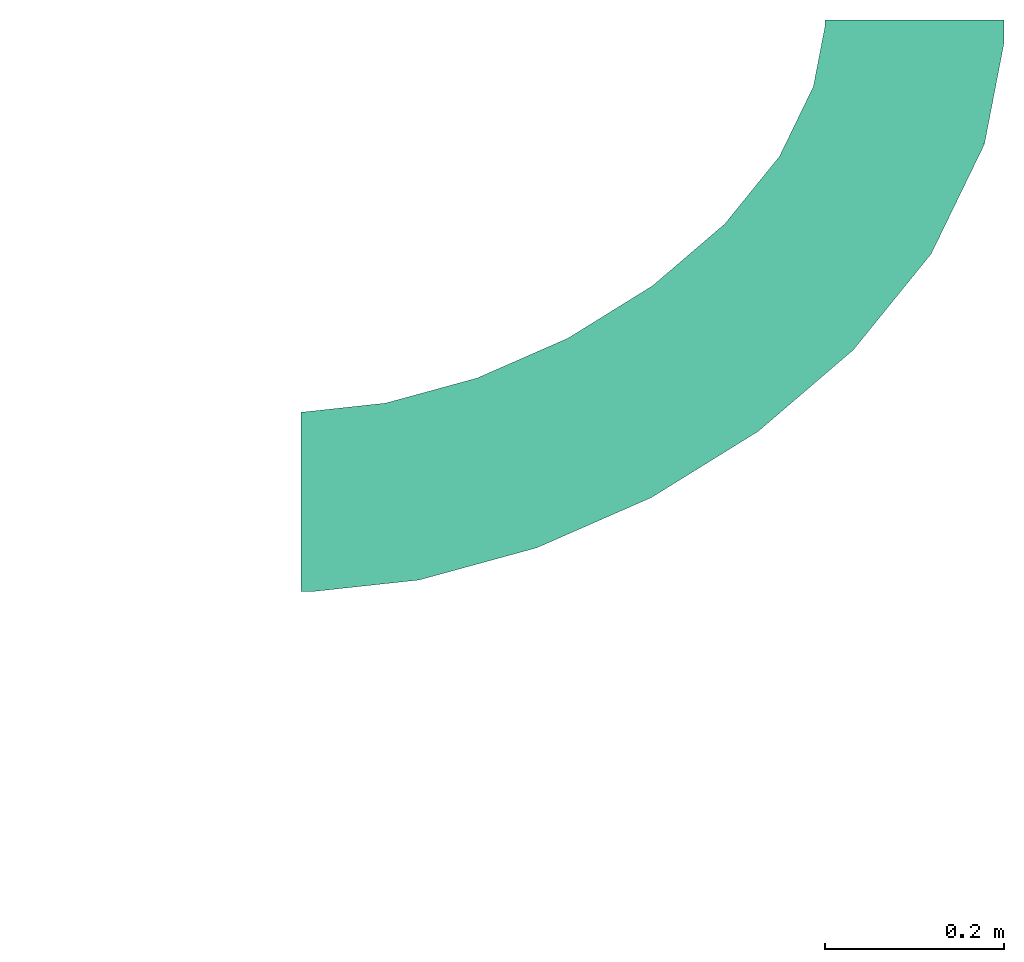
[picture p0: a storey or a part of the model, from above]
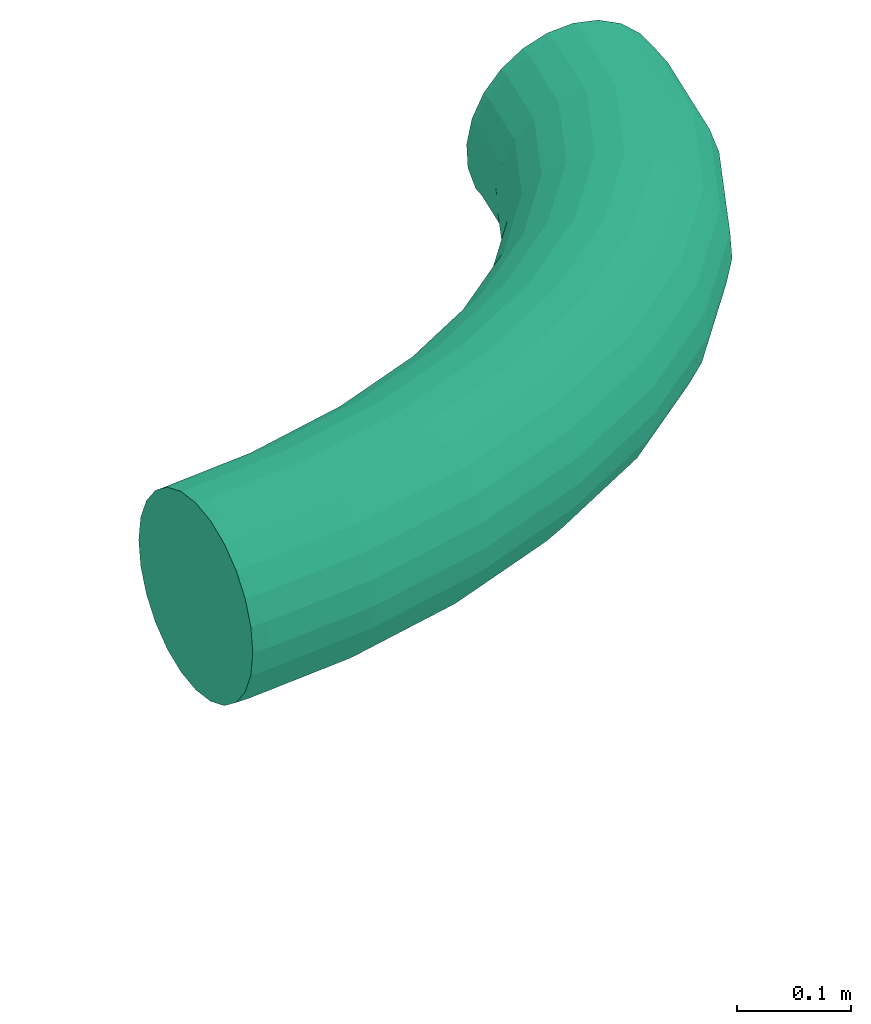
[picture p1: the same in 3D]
Properties of the parts of a building model (IFC2X3), part 1 of 2

# File
Description: ViewDefinition [CoordinationView_V2.0], RevitIdentifiers [ContentGUID: 55fdd698-1774-4c56-9708-9a2c424ac63d, VersionGUID: ae5423be-a13d-499d-9178-ae4d7e7fb8e4, NumberOfSaves: 309], CoordinateReference [CoordinateBase: Origem interna, ProjectSite: Terreno padrão]
File name: HVAC_ESCOLA DE CINEMA-CINE REX_01.ifc
Time: 2025-12-24T13:22:24-03:00
Written by: ODA SDAI 24.12
Made in: Autodesk Revit 25.3.0.46 (PTB) - IFC 25.3.0.46

# IfcProject, 0001
LongName: ESCOLA DE CINEMA E AUDIOVISUAL - CINE REX; Phase: AR CONDICIONADO

# IfcSite, Default
RefLatitude: -15, -52, 0, -120620; RefLongitude: -47, -55, 0, -114440; RefElevation: -6.76792e-14 mm

# IfcBuilding, Praça Pedro II, 1301 - Centro (Sul), Teresina - PI, 64001-100
LongName: Praça Pedro II, 1301 - Centro (Sul), Teresina - PI, 64001-100
Pset_BuildingCommon - NumberOfStoreys: 5

# IfcBuildingStorey: Nível:Cabeça de 8 mm (6)
In: Praça Pedro II, 1301 - Centro (Sul), Teresina - PI, 64001-100
Name | LongName | Elevation (mm)
TÉRREO -0.14m | TÉRREO -0.14m | -140
Nível 1 | Nível 1 | 0
TÉRREO +0.32m | TÉRREO +0.32m | 320
1PAV | 1PAV | 3020
2PAV | 2PAV | 6040
LAJE TÉCNICA | LAJE TÉCNICA | 9040

# IfcBuildingElementPart: QFACs:QFAC-1, QFACs:QFAC-1:884960
In: LAJE TÉCNICA
Type - Material: <Unnamed>
Pset_QuantityTakeOff - Reference: QFAC-1

# IfcBuildingElementProxy: Canvas Connection:Canvas Connection (8)
Type - Material: <Unnamed>
Pset_BuildingElementProxyCommon - Reference: Padrão; sets with these values: 2
Name (Canvas Connection:Padrão:...) | In
1067711 | 2PAV
1069002 | LAJE TÉCNICA
1069007 | LAJE TÉCNICA
1069011 | LAJE TÉCNICA
1069015 | LAJE TÉCNICA
1073034 | 1PAV
1084725 | 1PAV
1095775 | TÉRREO +0.32m

# IfcBuildingElementProxy: Família 40DV_Mod_Damper FanCoil:Tp05 40DV 670 (2)
In: LAJE TÉCNICA
Type - Material: <Unnamed>, Galvanizado
Type - Pset_ManufacturerTypeInformation - Manufacturer: Carrier do Brasil
Pset_BuildingElementProxyCommon - Reference: Tp05 40DV 670; sets with these values: 2
Name (Família 40DV_Mod_Damper FanCoil:Tp05 40DV 670:...)
872556
872802

# IfcBuildingElementProxy: Família 40DV_Mod_Troc_Vent FanCoil:Tp05 39DV 670 (2)
In: LAJE TÉCNICA
Type - Material: Galvanizado, Branco, Azul, <Unnamed>
Type - Pset_ManufacturerTypeInformation - Manufacturer: Carrier do Brasil
Pset_BuildingElementProxyCommon - Reference: Tp05 39DV 670; sets with these values: 2
Name (Família 40DV_Mod_Troc_Vent FanCoil:Tp05 39DV 670:...)
872605
872803

# IfcBuildingElementProxy: GLPF-200_1000-H-B-G4_M5:GLPF 280 (2)
In: LAJE TÉCNICA
Type - Material: Steel, Galvanized, Fabric
Type - Pset_ManufacturerTypeInformation - Manufacturer: Sicflux
Pset_BuildingElementProxyCommon - Reference: GLPF 280; sets with these values: 2
Name (GLPF-200_1000-H-B-G4_M5:GLPF 280:...) | Group
1087751 | AE 23
1088407 | AE 26

# IfcBuildingElementProxy: MIH100(140)DLHN18 (provisório):MIH160DLHN18, MIH100(140)DLHN18 (provisório):MIH160DLHN18:784083
In: 2PAV
Type - Material: Galvanized Steel, <Unnamed>
Pset_BuildingElementProxyCommon - Reference: MIH160DLHN18; sets with these values: 2

# IfcBuildingElementProxy: MULT VORTEX PAREDE:Tipo 1, MULT VORTEX PAREDE:Tipo 1:1112884
In: TÉRREO +0.32m
Type - Material: INOX ESCOVADO, INOX
Pset_BuildingElementProxyCommon - Reference: Tipo 1; sets with these values: 2
Group: EX 11

# IfcBuildingElementProxy: M_Control Damper - Opposed Blade (Type):100X105, M_Control Damper - Opposed Blade (Type):100X105:923647
In: TÉRREO +0.32m
Type - Material: <Unnamed>
Pset_BuildingElementProxyCommon - Reference: 100X105; sets with these values: 2
Group: AE 23

# IfcBuildingElementProxy: M_Control Damper - Opposed Blade (Type):100X155, M_Control Damper - Opposed Blade (Type):100X155:951628
In: 2PAV
Type - Material: <Unnamed>
Pset_BuildingElementProxyCommon - Reference: 100X155; sets with these values: 2
Group: AE 2

# IfcBuildingElementProxy: M_Control Damper - Opposed Blade (Type):200x155, M_Control Damper - Opposed Blade (Type):200x155:1071531
In: 1PAV
Type - Material: <Unnamed>
Pset_BuildingElementProxyCommon - Reference: 200x155; sets with these values: 2
Group: AE 13

# IfcBuildingElementProxy: Midea_VRF_Outdoor_MVCMax-M615(670,730,785,850)WV2GN1(50_60Hz):MVC-M670WV2GN1 (2)
In: LAJE TÉCNICA
Type - Material: Galvanized Steel
Type - Pset_ManufacturerTypeInformation - Manufacturer: Midea
Material: <Unnamed>, White, Dark Blue, Galvanized Steel
Pset_BuildingElementProxyCommon - Reference: MVC-M670WV2GN1; sets with these values: 2
Name (Midea_VRF_Outdoor_MVCMax-M615(670,730,785,850)WV2GN1(50_60Hz):MVC-M670WV2GN1:...)
792057
792070

# IfcBuildingElementProxy: Midea_VRF_Outdoor_MVCMax-M615(670,730,785,850)WV2GN1(50_60Hz):MVC-M785WV2GN1 (3)
In: LAJE TÉCNICA
Type - Material: Galvanized Steel
Type - Pset_ManufacturerTypeInformation - Manufacturer: Midea
Material: <Unnamed>, White, Dark Blue, Galvanized Steel
Pset_BuildingElementProxyCommon - Reference: MVC-M785WV2GN1; sets with these values: 2
Name (Midea_VRF_Outdoor_MVCMax-M615(670,730,785,850)WV2GN1(50_60Hz):MVC-M785WV2GN1:...)
792090
792099
883997

# IfcBuildingElementProxy: SGSD 277_457:SGSD 277, SGSD 277_457:SGSD 277:1084501
In: 1PAV
Type - Material: Steel, Galvanized
Type - Pset_ManufacturerTypeInformation - Manufacturer: Sicflux
Pset_BuildingElementProxyCommon - Reference: SGSD 277; sets with these values: 2
Group: AE 13; AE 24

# IfcBuildingElementProxy: SPLITVENT_BTS:SPLITVENT G4+M5, SPLITVENT_BTS:SPLITVENT G4+M5:1081998
In: 2PAV
Type - Material: Acetinado, Centra Fan - Body
Pset_BuildingElementProxyCommon - Reference: SPLITVENT G4+M5; sets with these values: 2

# IfcBuildingElementProxy: V8 Hi Wall 1.5-3.6kW Revit:2.2kW, V8 Hi Wall 1.5-3.6kW Revit:2.2kW:864359
In: TÉRREO +0.32m
Type - Material: Galvanized Steel, <Unnamed>
Pset_BuildingElementProxyCommon - Reference: 2.2kW; sets with these values: 2

# IfcBuildingElementProxy: V8 Hi Wall 1.5-3.6kW Revit:2.8kW (2)
Type - Material: Galvanized Steel, <Unnamed>
Pset_BuildingElementProxyCommon - Reference: 2.8kW; sets with these values: 2
Name (V8 Hi Wall 1.5-3.6kW Revit:2.8kW:...) | In
770520 | TÉRREO +0.32m
872139 | 2PAV

# IfcBuildingElementProxy: V8 Hi Wall 1.5-3.6kW Revit:3.6kW, V8 Hi Wall 1.5-3.6kW Revit:3.6kW:948295
In: 2PAV
Type - Material: Galvanized Steel, <Unnamed>
Pset_BuildingElementProxyCommon - Reference: 3.6kW; sets with these values: 2

# IfcBuildingElementProxy: V8 K7 4V 16.0-18.0kW:MIH160Q4HN18 (2)
Type - Material: Midea White, grilles：ABS/HIPS
Pset_BuildingElementProxyCommon - Reference: MIH160Q4HN18; sets with these values: 2
Name (V8 K7 4V 16.0-18.0kW:MIH160Q4HN18:...) | In
753553 | TÉRREO +0.32m
936077 | 2PAV

# IfcBuildingElementProxy: V8 K7 4V 2.8-8.0kW:MIH28Q4HN18, V8 K7 4V 2.8-8.0kW:MIH28Q4HN18:872213
In: 2PAV
Type - Material: Midea White, grilles：ABS/HIPS
Pset_BuildingElementProxyCommon - Reference: MIH28Q4HN18; sets with these values: 2

# IfcBuildingElementProxy: V8 K7 4V 2.8-8.0kW:MIH45Q4HN18, V8 K7 4V 2.8-8.0kW:MIH45Q4HN18:784014
In: 2PAV
Type - Material: Midea White, grilles：ABS/HIPS
Pset_BuildingElementProxyCommon - Reference: MIH45Q4HN18; sets with these values: 2

# IfcBuildingElementProxy: V8 K7 4V 2.8-8.0kW:MIH56Q4HN18, V8 K7 4V 2.8-8.0kW:MIH56Q4HN18:871980
In: 2PAV
Type - Material: Midea White, grilles：ABS/HIPS
Pset_BuildingElementProxyCommon - Reference: MIH56Q4HN18; sets with these values: 2

# IfcBuildingElementProxy: V8 K7 4V 9.0-14.0kW:MIH100Q4HN18 (5)
In: 1PAV
Type - Material: Midea White, grilles：ABS/HIPS
Type - Pset_ManufacturerTypeInformation - Manufacturer: Midea
Pset_BuildingElementProxyCommon - Reference: MIH100Q4HN18; sets with these values: 2
Name (V8 K7 4V 9.0-14.0kW:MIH100Q4HN18:...)
780288
780299
869001
869040
869052

# IfcBuildingElementProxy: V8 K7 4V 9.0-14.0kW:MIH112Q4HN18 (3)
Type - Material: Midea White, grilles：ABS/HIPS
Type - Pset_ManufacturerTypeInformation - Manufacturer: Midea
Pset_BuildingElementProxyCommon - Reference: MIH112Q4HN18; sets with these values: 2
Name (V8 K7 4V 9.0-14.0kW:MIH112Q4HN18:...) | In
784062 | 2PAV
841499 | 1PAV
841638 | 1PAV

# IfcBuildingElementProxy: V8 One-way cassette 1.8-3.6kW Revit:2.8kW, V8 One-way cassette 1.8-3.6kW Revit:2.8kW:842424
In: 2PAV
Type - Material: grilles：ABS/HIPS
Pset_BuildingElementProxyCommon - Reference: 2.8kW; sets with these values: 2

# IfcBuildingElementProxy: V8 One-way cassette 4.5-7.1kW Revit:4.5kW (2)
In: 2PAV
Type - Material: grilles：ABS/HIPS
Pset_BuildingElementProxyCommon - Reference: 4.5kW; sets with these values: 2
Name (V8 One-way cassette 4.5-7.1kW Revit:4.5kW:...)
842263
872043

# IfcBuildingElementProxy: V8 One-way cassette 4.5-7.1kW Revit:7.1kW (3)
Type - Material: grilles：ABS/HIPS
Pset_BuildingElementProxyCommon - Reference: 7.1kW; sets with these values: 2
Name (V8 One-way cassette 4.5-7.1kW Revit:7.1kW:...) | In
765319 | TÉRREO +0.32m
842596 | 2PAV
864236 | TÉRREO +0.32m

# IfcBuildingElementProxy: V8 duto alta 20-33.5kW:28kW (2)
Type - Material: Galvanized Steel, grilles：ABS/HIPS
Pset_BuildingElementProxyCommon - Reference: 28kW; sets with these values: 2
Name (V8 duto alta 20-33.5kW:28kW:...) | In | Group
869751 | 2PAV | R 5
882826 | 1PAV | I 5

# IfcBuildingElementProxy: V8 duto média 11.2-16.0kW:11.2kW, V8 duto média 11.2-16.0kW:11.2kW:868180
In: TÉRREO +0.32m
Type - Material: grilles：ABS/HIPS
Pset_BuildingElementProxyCommon - Reference: 11.2kW; sets with these values: 2
Group: R 3; I 8

# IfcBuildingElementProxy: VENTILADOR Titan LSC e LSF 200 a 1250:224 LSC (2)
In: LAJE TÉCNICA
Type - Material: VENTILADOS SIC, <Unnamed>, PRETO, cinza
Pset_BuildingElementProxyCommon - Reference: 224 LSC; sets with these values: 2
Name (VENTILADOR Titan LSC e LSF 200 a 1250:224 LSC:...) | Group
1063111 | EX 8; AE 20
1063151 | EX 3; AE 21

# IfcBuildingElementProxy: VENTILADOR Titan LSC e LSF 200 a 1250:250 LSC (2)
In: LAJE TÉCNICA
Type - Material: VENTILADOS SIC, <Unnamed>, PRETO, cinza
Pset_BuildingElementProxyCommon - Reference: 250 LSC; sets with these values: 2
Name (VENTILADOR Titan LSC e LSF 200 a 1250:250 LSC:...) | Group
1062948 | EX 1; AE 18
1063103 | EX 9; AE 19

# IfcBuildingElementProxy: VENTILADOR Titan LSC e LSF 200 a 1250:280 LSC, VENTILADOR Titan LSC e LSF 200 a 1250:280 LSC:1064072
In: LAJE TÉCNICA
Type - Material: VENTILADOS SIC, <Unnamed>, PRETO, cinza
Pset_BuildingElementProxyCommon - Reference: 280 LSC; sets with these values: 2
Group: EX 2; AE 22

# IfcBuildingElementProxy: VENTILADOR Titan LSC e LSF 200 a 1250:450 LSC, VENTILADOR Titan LSC e LSF 200 a 1250:450 LSC:1114082
In: LAJE TÉCNICA
Type - Material: VENTILADOS SIC, <Unnamed>, PRETO, cinza
Pset_BuildingElementProxyCommon - Reference: 450 LSC; sets with these values: 2
Group: EX 11; EX 10

# IfcDistributionPort (1531)
Description: Flow
Name | FlowDirection | Group
OutPort_753553_5 | SOURCE
Port_753553_6 | SOURCEANDSINK
Port_753553_7 | SOURCEANDSINK
Port_753553_8 | SOURCEANDSINK
Port_765319_4 | SOURCEANDSINK
Port_765319_5 | SOURCEANDSINK
OutPort_765319_6 | SOURCE
Port_765319_7 | SOURCEANDSINK
OutPort_770520_5 | SOURCE
Port_770520_6 | SOURCEANDSINK
Port_770520_7 | SOURCEANDSINK
Port_770520_8 | SOURCEANDSINK
OutPort_780288_5 | SOURCE
Port_780288_6 | SOURCEANDSINK
Port_780288_7 | SOURCEANDSINK
Port_780288_8 | SOURCEANDSINK
OutPort_780299_5 | SOURCE
Port_780299_6 | SOURCEANDSINK
Port_780299_7 | SOURCEANDSINK
Port_780299_8 | SOURCEANDSINK
OutPort_784014_5 | SOURCE
Port_784014_6 | SOURCEANDSINK
Port_784014_7 | SOURCEANDSINK
Port_784014_8 | SOURCEANDSINK
OutPort_784062_5 | SOURCE
Port_784062_6 | SOURCEANDSINK
Port_784062_7 | SOURCEANDSINK
Port_784062_8 | SOURCEANDSINK
OutPort_784083_5 | SOURCE
Port_784083_6 | SOURCEANDSINK
Port_784083_9 | SOURCEANDSINK
Port_792057_18 | SOURCEANDSINK
Port_792057_19 | SOURCEANDSINK
Port_792057_20 | SOURCEANDSINK
Port_792070_18 | SOURCEANDSINK
Port_792070_19 | SOURCEANDSINK
Port_792070_20 | SOURCEANDSINK
Port_792090_18 | SOURCEANDSINK
Port_792090_19 | SOURCEANDSINK
Port_792090_20 | SOURCEANDSINK
Port_792099_18 | SOURCEANDSINK
Port_792099_19 | SOURCEANDSINK
Port_792099_20 | SOURCEANDSINK
InPort_806109_2 | SINK | Mecânica Ar de fornecimento 1
OutPort_819979_0 | SOURCE | Mecânica Ar de fornecimento 1
InPort_806130_2 | SINK | Mecânica Ar de fornecimento 1
OutPort_819983_0 | SOURCE | Mecânica Ar de fornecimento 1
InPort_806138_2 | SINK | I 1
OutPort_820243_0 | SOURCE | I 1
InPort_806146_2 | SINK | I 1
OutPort_820247_1 | SOURCE | I 1
InPort_806156_2 | SINK | I 1
OutPort_820250_0 | SOURCE | I 1
InPort_806166_2 | SINK | I 1
OutPort_820259_0 | SOURCE | I 1
InPort_806176_2 | SINK | I 1
OutPort_820262_0 | SOURCE | I 1
InPort_806184_2 | SINK | I 1
OutPort_820271_0 | SOURCE | I 1
InPort_806205_2 | SINK | I 1
OutPort_820253_0 | SOURCE | I 1
InPort_806206_2 | SINK | I 1
OutPort_820256_0 | SOURCE | I 1
InPort_806207_2 | SINK | I 1
OutPort_820265_0 | SOURCE | I 1
InPort_806208_2 | SINK | I 1
OutPort_820268_0 | SOURCE | I 1
InPort_806216_2 | SINK | Mecânica Ar de fornecimento 1
OutPort_819986_0 | SOURCE | Mecânica Ar de fornecimento 1
InPort_806217_2 | SINK | Mecânica Ar de fornecimento 1
OutPort_819995_0 | SOURCE | Mecânica Ar de fornecimento 1
InPort_806218_2 | SINK | Mecânica Ar de fornecimento 1
OutPort_819998_0 | SOURCE | Mecânica Ar de fornecimento 1
InPort_806219_2 | SINK | Mecânica Ar de fornecimento 1
OutPort_820007_0 | SOURCE | Mecânica Ar de fornecimento 1
InPort_806227_2 | SINK | Mecânica Ar de fornecimento 1
OutPort_819989_0 | SOURCE | Mecânica Ar de fornecimento 1
InPort_806228_2 | SINK | Mecânica Ar de fornecimento 1
OutPort_819992_0 | SOURCE | Mecânica Ar de fornecimento 1
InPort_806229_2 | SINK | Mecânica Ar de fornecimento 1
OutPort_820001_0 | SOURCE | Mecânica Ar de fornecimento 1
InPort_806230_2 | SINK | Mecânica Ar de fornecimento 1
OutPort_820004_0 | SOURCE | Mecânica Ar de fornecimento 1
InPort_874549_1 | SINK | Mecânica Ar de fornecimento 1
OutPort_818453_0 | SOURCE | Mecânica Ar de fornecimento 1
InPort_818453_1 | SINK | Mecânica Ar de fornecimento 1
OutPort_873457_1 | SOURCE | Mecânica Ar de fornecimento 1
InPort_818453_4 | SINK | Mecânica Ar de fornecimento 1
OutPort_873459_1 | SOURCE | Mecânica Ar de fornecimento 1
InPort_818453_5 | SINK | Mecânica Ar de fornecimento 1
OutPort_873462_1 | SOURCE | Mecânica Ar de fornecimento 1
InPort_873556_1 | SINK | I 1
OutPort_818485_0 | SOURCE | I 1
InPort_818485_1 | SINK | I 1
OutPort_873502_1 | SOURCE | I 1
InPort_818485_4 | SINK | I 1
OutPort_873503_1 | SOURCE | I 1
InPort_818485_5 | SINK | I 1
OutPort_873505_1 | SOURCE | I 1
InPort_873457_2 | SINK | Mecânica Ar de fornecimento 1
OutPort_818510_0 | SOURCE | Mecânica Ar de fornecimento 1
InPort_818510_1 | SINK | Mecânica Ar de fornecimento 1
OutPort_873441_2 | SOURCE | Mecânica Ar de fornecimento 1
InPort_818510_2 | SINK | I 2
OutPort_819832_1 | SOURCE | I 2
InPort_818510_3 | SINK | I 2
OutPort_819874_1 | SOURCE | I 2
InPort_873502_2 | SINK | I 1
OutPort_818544_0 | SOURCE | I 1
InPort_818544_1 | SINK | I 1
OutPort_873513_2 | SOURCE | I 1
InPort_818544_2 | SINK | I 3
OutPort_820118_1 | SOURCE | I 3
InPort_818544_3 | SINK | I 3
OutPort_820128_1 | SOURCE | I 3
InPort_873441_1 | SINK | Mecânica Ar de fornecimento 1
OutPort_818567_0 | SOURCE | Mecânica Ar de fornecimento 1
InPort_818567_1 | SINK | Mecânica Ar de fornecimento 1
OutPort_873442_1 | SOURCE | Mecânica Ar de fornecimento 1
InPort_818567_4 | SINK | Mecânica Ar de fornecimento 1
OutPort_873444_1 | SOURCE | Mecânica Ar de fornecimento 1
InPort_818567_5 | SINK | Mecânica Ar de fornecimento 1
OutPort_873447_1 | SOURCE | Mecânica Ar de fornecimento 1
InPort_873513_1 | SINK | I 1
OutPort_818605_0 | SOURCE | I 1
InPort_818605_1 | SINK | I 1
OutPort_873514_1 | SOURCE | I 1
InPort_818605_2 | SINK | I 1
OutPort_876320_1 | SOURCE | I 1
InPort_818605_3 | SINK | I 1
OutPort_876328_1 | SOURCE | I 1
InPort_819832_1 | SINK | Mecânica Ar de fornecimento 1
OutPort_818510_2 | SOURCE | Mecânica Ar de fornecimento 1
InPort_819992_1 | SINK | Mecânica Ar de fornecimento 1
OutPort_819832_2 | SOURCE | Mecânica Ar de fornecimento 1
InPort_819874_1 | SINK | Mecânica Ar de fornecimento 1
OutPort_818510_3 | SOURCE | Mecânica Ar de fornecimento 1
InPort_819995_1 | SINK | Mecânica Ar de fornecimento 1
OutPort_819874_2 | SOURCE | Mecânica Ar de fornecimento 1
InPort_819979_1 | SINK | Mecânica Ar de fornecimento 1
OutPort_876085_2 | SOURCE | Mecânica Ar de fornecimento 1
InPort_819983_1 | SINK | Mecânica Ar de fornecimento 1
OutPort_876095_2 | SOURCE | Mecânica Ar de fornecimento 1
InPort_819986_1 | SINK | Mecânica Ar de fornecimento 1
OutPort_873459_2 | SOURCE | Mecânica Ar de fornecimento 1
InPort_819989_1 | SINK | Mecânica Ar de fornecimento 1
OutPort_873462_2 | SOURCE | Mecânica Ar de fornecimento 1
InPort_819998_1 | SINK | Mecânica Ar de fornecimento 1
OutPort_873444_2 | SOURCE | Mecânica Ar de fornecimento 1
InPort_820001_1 | SINK | Mecânica Ar de fornecimento 1
OutPort_873447_2 | SOURCE | Mecânica Ar de fornecimento 1
InPort_820004_1 | SINK | Mecânica Ar de fornecimento 1
OutPort_873420_2 | SOURCE | Mecânica Ar de fornecimento 1
InPort_820007_1 | SINK | Mecânica Ar de fornecimento 1
OutPort_873423_2 | SOURCE | Mecânica Ar de fornecimento 1
InPort_820118_1 | SINK | I 1
OutPort_818544_2 | SOURCE | I 1
InPort_820259_1 | SINK | I 1
OutPort_820118_2 | SOURCE | I 1
InPort_820128_1 | SINK | I 1
OutPort_818544_3 | SOURCE | I 1
InPort_820256_1 | SINK | I 1
OutPort_820128_2 | SOURCE | I 1
InPort_820243_1 | SINK | I 1
OutPort_876275_2 | SOURCE | I 1
InPort_820247_0 | SINK | I 1
OutPort_876241_2 | SOURCE | I 1
InPort_820250_1 | SINK | I 1
OutPort_873503_2 | SOURCE | I 1
InPort_820253_1 | SINK | I 1
OutPort_873505_2 | SOURCE | I 1
InPort_820262_1 | SINK | I 1
OutPort_876320_2 | SOURCE | I 1
InPort_820265_1 | SINK | I 1
OutPort_876328_2 | SOURCE | I 1
InPort_820268_1 | SINK | I 1
OutPort_874404_2 | SOURCE | I 1
InPort_820271_1 | SINK | I 1
OutPort_874430_2 | SOURCE | I 1
InPort_831728_1 | SINK | R 1
OutPort_829018_0 | SOURCE | R 1
Port_829018_1 | SOURCEANDSINK | R 1
Port_833313_1 | SOURCEANDSINK | R 1
InPort_829018_2 | SINK | R 1
OutPort_833305_1 | SOURCE | R 1
InPort_831641_1 | SINK | R 2
OutPort_829064_0 | SOURCE | R 2
Port_829064_1 | SOURCEANDSINK | R 2
Port_833358_1 | SOURCEANDSINK | R 2
InPort_829064_2 | SINK | R 2
OutPort_833351_1 | SOURCE | R 2
InPort_833251_0 | SINK | R 1
OutPort_830645_1 | SOURCE | R 1
InPort_833273_0 | SINK | R 1
OutPort_830682_1 | SOURCE | R 1
InPort_833288_0 | SINK | R 1
OutPort_830692_1 | SOURCE | R 1
InPort_833299_0 | SINK | R 1
OutPort_830700_1 | SOURCE | R 1
InPort_833347_0 | SINK | R 2
OutPort_830708_1 | SOURCE | R 2
InPort_833338_0 | SINK | R 2
OutPort_830732_1 | SOURCE | R 2
InPort_833329_0 | SINK | R 2
OutPort_830742_1 | SOURCE | R 2
InPort_833319_0 | SINK | R 2
OutPort_830750_1 | SOURCE | R 2
InPort_831099_0 | SINK | R 1
OutPort_831749_2 | SOURCE | R 1
InPort_878438_1 | SINK | R 1
OutPort_831099_1 | SOURCE | R 1
InPort_833259_1 | SINK | R 1
OutPort_831099_2 | SOURCE | R 1
InPort_831170_0 | SINK | R 1
OutPort_831748_2 | SOURCE | R 1
InPort_831749_1 | SINK | R 1
OutPort_831170_1 | SOURCE | R 1
InPort_833279_1 | SINK | R 1
OutPort_831170_2 | SOURCE | R 1
InPort_831225_0 | SINK | R 1
OutPort_831728_2 | SOURCE | R 1
InPort_831748_1 | SINK | R 1
OutPort_831225_1 | SOURCE | R 1
InPort_833294_1 | SINK | R 1
OutPort_831225_2 | SOURCE | R 1
InPort_831469_0 | SINK | R 2
OutPort_831686_2 | SOURCE | R 2
InPort_831687_1 | SINK | R 2
OutPort_831469_1 | SOURCE | R 2
InPort_833333_1 | SINK | R 2
OutPort_831469_2 | SOURCE | R 2
InPort_831545_0 | SINK | R 2
OutPort_831641_2 | SOURCE | R 2
InPort_831686_1 | SINK | R 2
OutPort_831545_1 | SOURCE | R 2
InPort_833342_1 | SINK | R 2
OutPort_831545_2 | SOURCE | R 2
InPort_875422_0 | SINK | R 2
OutPort_831687_2 | SOURCE | R 2
InPort_832806_0 | SINK | Mecânica Ar de fornecimento 1
OutPort_874549_2 | SOURCE | Mecânica Ar de fornecimento 1
Port_832806_1 | SOURCEANDSINK | Mecânica Ar de fornecimento 1
Port_874556_1 | SOURCEANDSINK | Mecânica Ar de fornecimento 1
InPort_876085_1 | SINK | Mecânica Ar de fornecimento 1
OutPort_832806_2 | SOURCE | Mecânica Ar de fornecimento 1
InPort_876095_1 | SINK | Mecânica Ar de fornecimento 1
OutPort_832806_3 | SOURCE | Mecânica Ar de fornecimento 1
InPort_832829_0 | SINK | I 1
OutPort_873556_2 | SOURCE | I 1
Port_832829_1 | SOURCEANDSINK | I 1
Port_875441_1 | SOURCEANDSINK | I 1
InPort_876241_1 | SINK | I 1
OutPort_832829_2 | SOURCE | I 1
InPort_876275_1 | SINK | I 1
OutPort_832829_3 | SOURCE | I 1
InPort_833259_2 | SINK | R 1
OutPort_833251_1 | SOURCE | R 1
InPort_831099_2 | SINK | R 1
OutPort_833259_1 | SOURCE | R 1
InPort_833279_2 | SINK | R 1
OutPort_833273_1 | SOURCE | R 1
InPort_831170_2 | SINK | R 1
OutPort_833279_1 | SOURCE | R 1
InPort_833294_2 | SINK | R 1
OutPort_833288_1 | SOURCE | R 1
InPort_831225_2 | SINK | R 1
OutPort_833294_1 | SOURCE | R 1
InPort_833305_2 | SINK | R 1
OutPort_833299_1 | SOURCE | R 1
InPort_833323_2 | SINK | R 2
OutPort_833319_1 | SOURCE | R 2
InPort_875422_2 | SINK | R 2
OutPort_833323_1 | SOURCE | R 2
InPort_833333_2 | SINK | R 2
OutPort_833329_1 | SOURCE | R 2
InPort_831469_2 | SINK | R 2
OutPort_833333_1 | SOURCE | R 2
InPort_833342_2 | SINK | R 2
OutPort_833338_1 | SOURCE | R 2
InPort_831545_2 | SINK | R 2
OutPort_833342_1 | SOURCE | R 2
InPort_833351_2 | SINK | R 2
OutPort_833347_1 | SOURCE | R 2
InPort_837886_1 | SINK | I 1
OutPort_837432_1 | SOURCE | I 1
InPort_837863_2 | SINK | I 1
OutPort_837524_1 | SOURCE | I 1
InPort_837854_0 | SINK | I 1
OutPort_837863_1 | SOURCE | I 1
InPort_838440_1 | SINK | I 1
OutPort_837854_1 | SOURCE | I 1
InPort_837879_0 | SINK | I 1
OutPort_837886_2 | SOURCE | I 1
InPort_838456_2 | SINK | I 1
OutPort_837879_1 | SOURCE | I 1
InPort_837887_0 | SINK | I 1
OutPort_838456_1 | SOURCE | I 1
InPort_838350_4 | SINK | I 1
OutPort_837887_1 | SOURCE | I 1
InPort_837912_0 | SINK | I 1
OutPort_838440_2 | SOURCE | I 1
InPort_838350_3 | SINK | I 1
OutPort_837912_1 | SOURCE | I 1
InPort_875039_1 | SINK | I 1
OutPort_838350_2 | SOURCE | I 1
InPort_838585_1 | SINK | Mecânica Ar de fornecimento 1
OutPort_838578_0 | SOURCE | Mecânica Ar de fornecimento 1
InPort_873376_2 | SINK | Mecânica Ar de fornecimento 1
OutPort_838579_0 | SOURCE | Mecânica Ar de fornecimento 1
InPort_838582_0 | SINK | Mecânica Ar de fornecimento 1
OutPort_873376_1 | SOURCE | Mecânica Ar de fornecimento 1
InPort_838589_1 | SINK | Mecânica Ar de fornecimento 1
OutPort_838582_1 | SOURCE | Mecânica Ar de fornecimento 1
InPort_838584_0 | SINK | Mecânica Ar de fornecimento 1
OutPort_838585_2 | SOURCE | Mecânica Ar de fornecimento 1
InPort_838590_2 | SINK | Mecânica Ar de fornecimento 1
OutPort_838584_1 | SOURCE | Mecânica Ar de fornecimento 1
InPort_838586_0 | SINK | Mecânica Ar de fornecimento 1
OutPort_838590_1 | SOURCE | Mecânica Ar de fornecimento 1
InPort_838588_4 | SINK | Mecânica Ar de fornecimento 1
OutPort_838586_1 | SOURCE | Mecânica Ar de fornecimento 1
InPort_838587_0 | SINK | Mecânica Ar de fornecimento 1
OutPort_838589_2 | SOURCE | Mecânica Ar de fornecimento 1
InPort_838588_3 | SINK | Mecânica Ar de fornecimento 1
OutPort_838587_1 | SOURCE | Mecânica Ar de fornecimento 1
InPort_838995_0 | SINK | Mecânica Ar de fornecimento 1
OutPort_838588_2 | SOURCE | Mecânica Ar de fornecimento 1
InPort_875176_1 | SINK | Mecânica Ar de fornecimento 1
OutPort_838995_1 | SOURCE | Mecânica Ar de fornecimento 1
OutPort_841499_5 | SOURCE
Port_841499_6 | SOURCEANDSINK
Port_841499_7 | SOURCEANDSINK
Port_841499_8 | SOURCEANDSINK
OutPort_841638_5 | SOURCE
Port_841638_6 | SOURCEANDSINK
Port_841638_7 | SOURCEANDSINK
Port_841638_8 | SOURCEANDSINK
Port_842263_4 | SOURCEANDSINK
Port_842263_5 | SOURCEANDSINK
OutPort_842263_6 | SOURCE
Port_842263_7 | SOURCEANDSINK
Port_842424_4 | SOURCEANDSINK
Port_842424_5 | SOURCEANDSINK
OutPort_842424_6 | SOURCE
Port_842424_7 | SOURCEANDSINK
Port_842596_4 | SOURCEANDSINK
Port_842596_5 | SOURCEANDSINK
OutPort_842596_6 | SOURCE
Port_842596_7 | SOURCEANDSINK
Port_864236_4 | SOURCEANDSINK
Port_864236_5 | SOURCEANDSINK
OutPort_864236_6 | SOURCE
Port_864236_7 | SOURCEANDSINK
OutPort_864359_5 | SOURCE
Port_864359_6 | SOURCEANDSINK
Port_864359_7 | SOURCEANDSINK
Port_864359_8 | SOURCEANDSINK
OutPort_868180_11 | SOURCE
Port_868180_16 | SOURCEANDSINK
Port_868180_17 | SOURCEANDSINK
Port_868180_18 | SOURCEANDSINK
Port_868180_21 | SOURCEANDSINK
Port_868180_22 | SOURCEANDSINK | R 3
Port_916132_0 | SOURCEANDSINK | R 3
Port_868180_23 | SOURCEANDSINK | I 8
OutPort_869001_5 | SOURCE
Port_869001_6 | SOURCEANDSINK
Port_869001_7 | SOURCEANDSINK
Port_869001_8 | SOURCEANDSINK
OutPort_869040_5 | SOURCE
Port_869040_6 | SOURCEANDSINK
Port_869040_7 | SOURCEANDSINK
Port_869040_8 | SOURCEANDSINK
OutPort_869052_5 | SOURCE
Port_869052_6 | SOURCEANDSINK
Port_869052_7 | SOURCEANDSINK
Port_869052_8 | SOURCEANDSINK
OutPort_869751_5 | SOURCE
InPort_869751_10 | SINK | R 5
OutPort_925507_0 | SOURCE | R 5
Port_869751_12 | SOURCEANDSINK
Port_869751_13 | SOURCEANDSINK
Port_869751_14 | SOURCEANDSINK
Port_869751_15 | SOURCEANDSINK
Port_869751_16 | SOURCEANDSINK
OutPort_871980_5 | SOURCE
Port_871980_6 | SOURCEANDSINK
Port_871980_7 | SOURCEANDSINK
Port_871980_8 | SOURCEANDSINK
Port_872043_4 | SOURCEANDSINK
Port_872043_5 | SOURCEANDSINK
OutPort_872043_6 | SOURCE
Port_872043_7 | SOURCEANDSINK
OutPort_872139_5 | SOURCE
Port_872139_6 | SOURCEANDSINK
Port_872139_7 | SOURCEANDSINK
Port_872139_8 | SOURCEANDSINK
OutPort_872213_5 | SOURCE
Port_872213_6 | SOURCEANDSINK
Port_872213_7 | SOURCEANDSINK
Port_872213_8 | SOURCEANDSINK
Port_872556_1 | SOURCEANDSINK
Port_872556_2 | SOURCEANDSINK
OutPort_872605_1 | SOURCE
InPort_872605_2 | SINK
OutPort_872605_4 | SOURCE
Port_872605_5 | SOURCEANDSINK
OutPort_872605_6 | SOURCE
Port_872605_11 | SOURCEANDSINK
OutPort_872605_12 | SOURCE
Port_872802_1 | SOURCEANDSINK
Port_872802_2 | SOURCEANDSINK
OutPort_872803_1 | SOURCE
InPort_872803_2 | SINK
OutPort_872803_4 | SOURCE
Port_872803_5 | SOURCEANDSINK
OutPort_872803_6 | SOURCE
Port_872803_11 | SOURCEANDSINK
OutPort_872803_12 | SOURCE
InPort_873420_1 | SINK | Mecânica Ar de fornecimento 1
OutPort_874741_3 | SOURCE | Mecânica Ar de fornecimento 1
InPort_873423_1 | SINK | Mecânica Ar de fornecimento 1
OutPort_874741_2 | SOURCE | Mecânica Ar de fornecimento 1
InPort_873442_2 | SINK | Mecânica Ar de fornecimento 1
OutPort_874741_0 | SOURCE | Mecânica Ar de fornecimento 1
InPort_873444_1 | SINK | Mecânica Ar de fornecimento 1
OutPort_818567_4 | SOURCE | Mecânica Ar de fornecimento 1
InPort_873447_1 | SINK | Mecânica Ar de fornecimento 1
OutPort_818567_5 | SOURCE | Mecânica Ar de fornecimento 1
InPort_873459_1 | SINK | Mecânica Ar de fornecimento 1
OutPort_818453_4 | SOURCE | Mecânica Ar de fornecimento 1
InPort_873462_1 | SINK | Mecânica Ar de fornecimento 1
OutPort_818453_5 | SOURCE | Mecânica Ar de fornecimento 1
InPort_873503_1 | SINK | I 1
OutPort_818485_4 | SOURCE | I 1
InPort_873505_1 | SINK | I 1
OutPort_818485_5 | SOURCE | I 1
InPort_873514_2 | SINK | I 1
OutPort_873656_0 | SOURCE | I 1
InPort_873656_1 | SINK | I 1
OutPort_874873_1 | SOURCE | I 1
InPort_873656_2 | SINK | I 1
OutPort_874404_1 | SOURCE | I 1
InPort_873656_3 | SINK | I 1
OutPort_874430_1 | SOURCE | I 1
InPort_874404_1 | SINK | I 1
OutPort_873656_2 | SOURCE | I 1
InPort_874430_1 | SINK | I 1
OutPort_873656_3 | SOURCE | I 1
InPort_874741_1 | SINK | Mecânica Ar de fornecimento 1
OutPort_874760_2 | SOURCE | Mecânica Ar de fornecimento 1
InPort_874741_2 | SINK | Mecânica Ar de fornecimento 1
OutPort_873423_1 | SOURCE | Mecânica Ar de fornecimento 1
InPort_874741_3 | SINK | Mecânica Ar de fornecimento 1
OutPort_873420_1 | SOURCE | Mecânica Ar de fornecimento 1
InPort_874760_1 | SINK | Mecânica Ar de fornecimento 1
OutPort_874750_0 | SOURCE | Mecânica Ar de fornecimento 1
InPort_874750_1 | SINK | Mecânica Ar de fornecimento 1
OutPort_874805_1 | SOURCE | Mecânica Ar de fornecimento 1
InPort_874805_2 | SINK | Mecânica Ar de fornecimento 1
OutPort_874806_0 | SOURCE | Mecânica Ar de fornecimento 1
InPort_874806_1 | SINK | Mecânica Ar de fornecimento 1
OutPort_875174_1 | SOURCE | Mecânica Ar de fornecimento 1
InPort_874873_2 | SINK | I 1
OutPort_874866_0 | SOURCE | I 1
InPort_874866_1 | SINK | I 1
OutPort_874880_2 | SOURCE | I 1
InPort_874880_1 | SINK | I 1
OutPort_874875_0 | SOURCE | I 1
InPort_874875_1 | SINK | I 1
OutPort_875036_1 | SOURCE | I 1
InPort_875036_2 | SINK | I 1
OutPort_875021_0 | SOURCE | I 1
InPort_875021_1 | SINK | I 1
OutPort_875070_1 | SOURCE | I 1
InPort_875070_2 | SINK | I 1
OutPort_875039_0 | SOURCE | I 1
InPort_875174_2 | SINK | Mecânica Ar de fornecimento 1
OutPort_875102_0 | SOURCE | Mecânica Ar de fornecimento 1
InPort_875102_1 | SINK | Mecânica Ar de fornecimento 1
OutPort_875176_2 | SOURCE | Mecânica Ar de fornecimento 1
InPort_878363_2 | SINK | R 2
OutPort_875422_1 | SOURCE | R 2
InPort_833323_1 | SINK | R 2
OutPort_875422_2 | SOURCE | R 2
InPort_876320_1 | SINK | I 1
OutPort_818605_2 | SOURCE | I 1
InPort_876328_1 | SINK | I 1
OutPort_818605_3 | SOURCE | I 1
InPort_878356_0 | SINK | R 2
OutPort_878363_1 | SOURCE | R 2
InPort_878412_1 | SINK | R 2
OutPort_878356_1 | SOURCE | R 2
InPort_878405_0 | SINK | R 2
OutPort_878412_2 | SOURCE | R 2
InPort_878595_1 | SINK | R 2
OutPort_878405_1 | SOURCE | R 2
InPort_878431_0 | SINK | R 1
OutPort_878438_2 | SOURCE | R 1
InPort_878444_2 | SINK | R 1
OutPort_878431_1 | SOURCE | R 1
InPort_878439_0 | SINK | R 1
OutPort_878444_1 | SOURCE | R 1
InPort_878476_1 | SINK | R 1
OutPort_878439_1 | SOURCE | R 1
InPort_878469_0 | SINK | R 1
OutPort_878476_2 | SOURCE | R 1
InPort_878857_1 | SINK | R 1
OutPort_878469_1 | SOURCE | R 1
InPort_1068476_1 | SINK | R 1
OutPort_878479_0 | SOURCE | R 1
InPort_878479_1 | SINK | R 1
OutPort_1068477_2 | SOURCE | R 1
InPort_878614_0 | SINK | R 2
OutPort_878595_2 | SOURCE | R 2
InPort_1068906_1 | SINK | R 2
OutPort_878614_1 | SOURCE | R 2
InPort_878816_0 | SINK | R 2
OutPort_878823_1 | SOURCE | R 2
OutPort_878816_1 | SOURCE | R 2
InPort_1068955_1 | SINK | R 2
OutPort_878816_2 | SOURCE | R 2
InPort_878823_2 | SINK | R 2
OutPort_1068919_0 | SOURCE | R 2
InPort_1068402_0 | SINK | R 1
OutPort_878857_2 | SOURCE | R 1
InPort_878860_0 | SINK | R 1
OutPort_1068476_2 | SOURCE | R 1
OutPort_878860_1 | SOURCE | R 1
InPort_1068689_1 | SINK | R 1
OutPort_878860_2 | SOURCE | R 1
OutPort_882826_5 | SOURCE
Port_882826_10 | SOURCEANDSINK
Port_882826_12 | SOURCEANDSINK
Port_882826_13 | SOURCEANDSINK
Port_882826_14 | SOURCEANDSINK | I 5
Port_882826_15 | SOURCEANDSINK
Port_882826_16 | SOURCEANDSINK | I 5
Port_883997_18 | SOURCEANDSINK
Port_883997_19 | SOURCEANDSINK
Port_883997_20 | SOURCEANDSINK
OutPort_888307_1 | SOURCE
OutPort_888325_1 | SOURCE
Port_894178_1 | SOURCEANDSINK | I 5
Port_895242_0 | SOURCEANDSINK | I 5
Port_894400_1 | SOURCEANDSINK | I 5
Port_895264_0 | SOURCEANDSINK | I 5
Port_894408_1 | SOURCEANDSINK | I 5
Port_895284_0 | SOURCEANDSINK | I 5
Port_894418_1 | SOURCEANDSINK | I 5
Port_895308_0 | SOURCEANDSINK | I 5
Port_894426_1 | SOURCEANDSINK | I 5
Port_895330_0 | SOURCEANDSINK | I 5
Port_894785_0 | SOURCEANDSINK | I 5
Port_895529_1 | SOURCEANDSINK | I 5
Port_894785_1 | SOURCEANDSINK | I 5
Port_895570_1 | SOURCEANDSINK | I 5
Port_894785_4 | SOURCEANDSINK | I 5
Port_895366_1 | SOURCEANDSINK | I 5
Port_894785_5 | SOURCEANDSINK | I 5
Port_895404_1 | SOURCEANDSINK | I 5
Port_894785_6 | SOURCEANDSINK | I 5
Port_895437_1 | SOURCEANDSINK | I 5
Port_894785_7 | SOURCEANDSINK | I 5
Port_895468_1 | SOURCEANDSINK | I 5
Port_894785_8 | SOURCEANDSINK | I 5
Port_895501_1 | SOURCEANDSINK | I 5
Port_894785_9 | SOURCEANDSINK | I 5
Port_1072892_1 | SOURCEANDSINK | I 5
Port_895242_1 | SOURCEANDSINK | I 5
Port_895501_2 | SOURCEANDSINK | I 5
Port_895264_1 | SOURCEANDSINK | I 5
Port_895468_2 | SOURCEANDSINK | I 5
Port_895284_1 | SOURCEANDSINK | I 5
Port_895437_2 | SOURCEANDSINK | I 5
Port_895308_1 | SOURCEANDSINK | I 5
Port_895404_2 | SOURCEANDSINK | I 5
Port_895330_1 | SOURCEANDSINK | I 5
Port_895366_2 | SOURCEANDSINK | I 5
InPort_896588_1 | SINK
InPort_898182_1 | SINK | AE 3
OutPort_923890_1 | SOURCE | AE 3
InPort_899065_1 | SINK | AE 3
OutPort_1124093_0 | SOURCE | AE 3
InPort_899070_1 | SINK | AE 3
OutPort_923757_0 | SOURCE | AE 3
InPort_899104_1 | SINK | AE 3
OutPort_1124044_0 | SOURCE | AE 3
InPort_899176_1 | SINK | AE 23
OutPort_924303_0 | SOURCE | AE 23
InPort_902440_1 | SINK | I 6
OutPort_910736_0 | SOURCE | I 6
InPort_902462_1 | SINK | I 6
OutPort_910820_0 | SOURCE | I 6
InPort_902470_1 | SINK | I 6
OutPort_910905_0 | SOURCE | I 6
InPort_902480_1 | SINK | I 6
OutPort_910989_0 | SOURCE | I 6
InPort_902786_0 | SINK | I 6
OutPort_902816_1 | SOURCE | I 6
Port_902786_1 | SOURCEANDSINK | I 6
Port_911081_1 | SOURCEANDSINK | I 6
InPort_911044_1 | SINK | I 6
OutPort_902786_2 | SOURCE | I 6
InPort_902816_2 | SINK | I 6
OutPort_902793_0 | SOURCE | I 6
InPort_902793_1 | SINK | I 6
OutPort_902839_1 | SOURCE | I 6
InPort_902793_2 | SINK | I 7
OutPort_910975_1 | SOURCE | I 7
InPort_902839_2 | SINK | I 6
OutPort_902818_0 | SOURCE | I 6
InPort_902818_1 | SINK | I 6
OutPort_902858_1 | SOURCE | I 6
InPort_902818_2 | SINK | I 4
OutPort_910890_1 | SOURCE | I 4
InPort_902858_2 | SINK | I 6
OutPort_903864_0 | SOURCE | I 6
InPort_903864_1 | SINK | I 6
OutPort_903880_2 | SOURCE | I 6
InPort_903864_2 | SINK | I 6
OutPort_910805_1 | SOURCE | I 6
InPort_903880_1 | SINK | I 6
OutPort_903871_0 | SOURCE | I 6
InPort_903871_1 | SINK | I 6
OutPort_903886_1 | SOURCE | I 6
InPort_903886_2 | SINK | I 6
OutPort_903881_0 | SOURCE | I 6
InPort_903881_1 | SINK | I 6
OutPort_925227_1 | SOURCE | I 6
InPort_904946_1 | SINK | EX 2
OutPort_912508_2 | SOURCE | EX 2
InPort_905042_1 | SINK | EX 2
OutPort_906717_0 | SOURCE | EX 2
InPort_905049_1 | SINK | EX 3
OutPort_906687_0 | SOURCE | EX 3
InPort_905104_1 | SINK | EX 3
OutPort_905274_0 | SOURCE | EX 3
InPort_905111_1 | SINK | EX 2
OutPort_905256_0 | SOURCE | EX 2
InPort_905256_1 | SINK | EX 2
OutPort_907281_2 | SOURCE | EX 2
InPort_905274_1 | SINK | EX 3
OutPort_911653_2 | SOURCE | EX 3
InPort_906351_1 | SINK | EX 2
OutPort_906409_0 | SOURCE | EX 2
InPort_906409_1 | SINK | EX 2
OutPort_1125579_2 | SOURCE | EX 2
InPort_906563_0 | SINK | EX 2
OutPort_906587_2 | SOURCE | EX 2
Port_906563_1 | SOURCEANDSINK | EX 2
Port_1125596_1 | SOURCEANDSINK | EX 2
InPort_1125579_1 | SINK | EX 2
OutPort_906563_2 | SOURCE | EX 2
InPort_906587_1 | SINK | EX 2
OutPort_906570_0 | SOURCE | EX 2
InPort_906570_1 | SINK | EX 2
OutPort_906595_1 | SOURCE | EX 2
InPort_906595_2 | SINK | EX 2
OutPort_906588_0 | SOURCE | EX 2
InPort_906588_1 | SINK | EX 2
OutPort_907081_1 | SOURCE | EX 2
InPort_907081_2 | SINK | EX 2
OutPort_906622_0 | SOURCE | EX 2
InPort_906622_1 | SINK | EX 2
OutPort_907079_2 | SOURCE | EX 2
InPort_906687_1 | SINK | EX 3
OutPort_911679_1 | SOURCE | EX 3
InPort_911681_2 | SINK | EX 3
OutPort_906694_0 | SOURCE | EX 3
InPort_906694_1 | SINK | EX 3
OutPort_1064322_1 | SOURCE | EX 3
InPort_906694_2 | SINK | EX 3
OutPort_911653_1 | SOURCE | EX 3
InPort_906717_1 | SINK | EX 2
OutPort_906759_1 | SOURCE | EX 2
InPort_906759_2 | SINK | EX 2
OutPort_906726_0 | SOURCE | EX 2
InPort_906726_1 | SINK | EX 2
OutPort_906836_2 | SOURCE | EX 2
InPort_906836_1 | SINK | EX 2
OutPort_907122_0 | SOURCE | EX 2
InPort_907079_1 | SINK | EX 2
OutPort_907122_3 | SOURCE | EX 2
InPort_907122_1 | SINK | EX 2
OutPort_907222_1 | SOURCE | EX 2
InPort_907122_3 | SINK | EX 5
OutPort_907079_1 | SOURCE | EX 5
InPort_907122_4 | SINK | EX 2
OutPort_912506_1 | SOURCE | EX 2
InPort_907222_2 | SINK | EX 2
OutPort_907211_0 | SOURCE | EX 2
InPort_907211_1 | SINK | EX 2
OutPort_911886_1 | SOURCE | EX 2
InPort_907211_2 | SINK | EX 2
OutPort_907281_1 | SOURCE | EX 2
InPort_907281_1 | SINK | EX 2
OutPort_907211_2 | SOURCE | EX 2
InPort_908131_1 | SINK | EX 1
OutPort_1127089_0 | SOURCE | EX 1
InPort_908138_1 | SINK | EX 1
OutPort_1127072_0 | SOURCE | EX 1
InPort_908145_1 | SINK | EX 1
OutPort_1127053_0 | SOURCE | EX 1
InPort_908652_0 | SINK | EX 1
OutPort_908670_1 | SOURCE | EX 1
Port_908652_1 | SOURCEANDSINK | EX 1
Port_908977_1 | SOURCEANDSINK | EX 1
InPort_1127095_1 | SINK | EX 1
OutPort_908652_2 | SOURCE | EX 1
InPort_908670_2 | SINK | EX 1
OutPort_908659_0 | SOURCE | EX 1
InPort_908659_1 | SINK | EX 1
OutPort_908695_1 | SOURCE | EX 1
InPort_908659_2 | SINK | EX 1
OutPort_1127080_1 | SOURCE | EX 1
InPort_908695_2 | SINK | EX 1
OutPort_908865_0 | SOURCE | EX 1
InPort_908865_1 | SINK | EX 1
OutPort_910574_1 | SOURCE | EX 1
InPort_908865_2 | SINK | EX 1
OutPort_1127062_1 | SOURCE | EX 1
InPort_910574_2 | SINK | EX 1
OutPort_908876_0 | SOURCE | EX 1
InPort_908876_1 | SINK | EX 1
OutPort_910586_1 | SOURCE | EX 1
InPort_908985_1 | SINK | EX 8
OutPort_909444_0 | SOURCE | EX 8
InPort_908992_1 | SINK | EX 8
OutPort_909281_0 | SOURCE | EX 8
Port_909018_0 | SOURCEANDSINK | EX 8
Port_910560_1 | SOURCEANDSINK | EX 8
InPort_909018_1 | SINK | EX 8
OutPort_909034_1 | SOURCE | EX 8
Port_909018_2 | SOURCEANDSINK | EX 8
Port_909597_1 | SOURCEANDSINK | EX 8
InPort_909034_2 | SINK | EX 8
OutPort_909023_0 | SOURCE | EX 8
InPort_909023_1 | SINK | EX 8
OutPort_909076_2 | SOURCE | EX 8
InPort_909023_2 | SINK | EX 8
OutPort_909431_1 | SOURCE | EX 8
InPort_909076_1 | SINK | EX 8
OutPort_909618_0 | SOURCE | EX 8
InPort_909281_1 | SINK | EX 8
OutPort_909431_2 | SOURCE | EX 8
InPort_909431_1 | SINK | EX 8
OutPort_909023_2 | SOURCE | EX 8
InPort_909444_1 | SINK | EX 8
OutPort_909597_2 | SOURCE | EX 8
InPort_909597_1 | SINK | EX 8
OutPort_909018_2 | SOURCE | EX 8
InPort_909618_1 | SINK | EX 8
OutPort_1127409_1 | SOURCE | EX 8
InPort_909626_0 | SINK | EX 8
OutPort_1127370_2 | SOURCE | EX 8
InPort_1127386_1 | SINK | EX 8
OutPort_909626_1 | SOURCE | EX 8
InPort_909680_1 | SINK | EX 9
OutPort_909909_0 | SOURCE | EX 9
InPort_909709_1 | SINK | EX 9
OutPort_910001_0 | SOURCE | EX 9
InPort_909725_1 | SINK | EX 9
OutPort_910090_0 | SOURCE | EX 9
Port_909759_0 | SOURCEANDSINK | EX 9
Port_909989_1 | SOURCEANDSINK | EX 9
InPort_909759_1 | SINK | EX 9
OutPort_1129736_1 | SOURCE | EX 9
Port_909759_2 | SOURCEANDSINK | EX 9
Port_909977_1 | SOURCEANDSINK | EX 9
InPort_1129736_2 | SINK | EX 9
OutPort_909766_0 | SOURCE | EX 9
InPort_909766_1 | SINK | EX 9
OutPort_1129737_1 | SOURCE | EX 9
InPort_909766_3 | SINK | EX 9
OutPort_1129495_1 | SOURCE | EX 9
InPort_1129737_2 | SINK | EX 9
OutPort_909811_0 | SOURCE | EX 9
InPort_909811_1 | SINK | EX 9
OutPort_910186_1 | SOURCE | EX 9
InPort_909811_2 | SINK | EX 9
OutPort_910147_1 | SOURCE | EX 9
InPort_909909_1 | SINK | EX 9
OutPort_909977_2 | SOURCE | EX 9
InPort_909977_1 | SINK | EX 9
OutPort_909759_2 | SOURCE | EX 9
InPort_910001_1 | SINK | EX 9
OutPort_1129495_2 | SOURCE | EX 9
InPort_910090_1 | SINK | EX 9
OutPort_910147_2 | SOURCE | EX 9
InPort_910147_1 | SINK | EX 9
OutPort_909811_2 | SOURCE | EX 9
InPort_910186_2 | SINK | EX 9
OutPort_910179_0 | SOURCE | EX 9
InPort_910179_1 | SINK | EX 9
OutPort_1127336_1 | SOURCE | EX 9
InPort_910586_2 | SINK | EX 1
OutPort_910577_0 | SOURCE | EX 1
InPort_910577_1 | SINK | EX 1
OutPort_910595_1 | SOURCE | EX 1
InPort_910595_2 | SINK | EX 1
OutPort_910590_0 | SOURCE | EX 1
InPort_910590_1 | SINK | EX 1
OutPort_1127168_1 | SOURCE | EX 1
InPort_910736_1 | SINK | I 6
OutPort_910805_2 | SOURCE | I 6
InPort_910805_1 | SINK | I 6
OutPort_903864_2 | SOURCE | I 6
InPort_910820_1 | SINK | I 6
OutPort_910890_2 | SOURCE | I 6
InPort_910890_1 | SINK | I 6
OutPort_902818_2 | SOURCE | I 6
InPort_910905_1 | SINK | I 6
OutPort_910975_2 | SOURCE | I 6
InPort_910975_1 | SINK | I 6
OutPort_902793_2 | SOURCE | I 6
InPort_910989_1 | SINK | I 6
OutPort_911044_2 | SOURCE | I 6
InPort_911679_2 | SINK | EX 3
OutPort_911629_0 | SOURCE | EX 3
InPort_911629_1 | SINK | EX 3
OutPort_911681_1 | SOURCE | EX 3
InPort_911653_1 | SINK | EX 3
OutPort_906694_2 | SOURCE | EX 3
InPort_1064322_2 | SINK | EX 3
OutPort_911733_0 | SOURCE | EX 3
InPort_911733_1 | SINK | EX 3
OutPort_1064336_1 | SOURCE | EX 3
InPort_911886_2 | SINK | EX 2
OutPort_911760_0 | SOURCE | EX 2
InPort_911760_1 | SINK | EX 2
OutPort_911896_1 | SOURCE | EX 2
InPort_911896_2 | SINK | EX 2
OutPort_911889_0 | SOURCE | EX 2
InPort_911889_1 | SINK | EX 2
OutPort_1064215_1 | SOURCE | EX 2
InPort_912497_0 | SINK | EX 2
OutPort_912506_2 | SOURCE | EX 2
InPort_912508_1 | SINK | EX 2
OutPort_912497_1 | SOURCE | EX 2
InPort_912506_1 | SINK | EX 2
OutPort_907122_4 | SOURCE | EX 2
InPort_1127168_2 | SINK | EX 1
OutPort_912546_0 | SOURCE | EX 1
InPort_912546_1 | SINK | EX 1
OutPort_1127170_0 | SOURCE | EX 1
InPort_1127370_1 | SINK | EX 8
OutPort_912595_0 | SOURCE | EX 8
InPort_912595_1 | SINK | EX 8
OutPort_1063996_0 | SOURCE | EX 8
InPort_912745_2 | SINK | I 8
OutPort_914768_1 | SOURCE | I 8
InPort_912785_2 | SINK | I 8
OutPort_914830_1 | SOURCE | I 8
InPort_913396_2 | SINK | I 8
OutPort_914826_0 | SOURCE | I 8
InPort_913450_2 | SINK | I 8
OutPort_914765_0 | SOURCE | I 8
InPort_913915_0 | SINK | I 8
OutPort_1095808_1 | SOURCE | I 8
InPort_1120141_1 | SINK | I 8
OutPort_913915_1 | SOURCE | I 8
InPort_1134652_1 | SINK | I 8
OutPort_913915_2 | SOURCE | I 8
InPort_1134660_1 | SINK | I 8
OutPort_913915_3 | SOURCE | I 8
Port_913974_0 | SOURCEANDSINK | I 8
Port_914011_1 | SOURCEANDSINK | I 8
InPort_913974_1 | SINK | I 8
OutPort_1120182_1 | SOURCE | I 8
Port_913974_2 | SOURCEANDSINK | I 8
Port_1134556_1 | SOURCEANDSINK | I 8
Port_913974_3 | SOURCEANDSINK | I 8
Port_1134591_1 | SOURCEANDSINK | I 8
InPort_914765_1 | SINK | I 8
OutPort_1134652_2 | SOURCE | I 8
InPort_914768_0 | SINK | I 8
OutPort_1134660_2 | SOURCE | I 8
InPort_914826_1 | SINK | I 8
OutPort_1134591_2 | SOURCE | I 8
InPort_914830_0 | SINK | I 8
OutPort_1134556_2 | SOURCE | I 8
Port_916132_1 | SOURCEANDSINK | R 3
Port_918098_1 | SOURCEANDSINK | R 3
InPort_917817_1 | SINK | R 3
OutPort_947193_0 | SOURCE | R 3
InPort_919662_0 | SINK | R 5
OutPort_919003_1 | SOURCE | R 5
InPort_919560_0 | SINK | R 5
OutPort_919010_1 | SOURCE | R 5
InPort_919536_1 | SINK | R 5
OutPort_919029_1 | SOURCE | R 5
InPort_919431_0 | SINK | R 5
OutPort_919037_1 | SOURCE | R 5
Port_919055_0 | SOURCEANDSINK | R 5
Port_919225_1 | SOURCEANDSINK | R 5
InPort_919132_1 | SINK | R 5
OutPort_919055_1 | SOURCE | R 5
Port_919055_2 | SOURCEANDSINK | R 5
Port_919521_1 | SOURCEANDSINK | R 5
InPort_919121_0 | SINK | R 5
OutPort_919132_2 | SOURCE | R 5
InPort_919165_1 | SINK | R 5
OutPort_919121_1 | SOURCE | R 5
InPort_919550_1 | SINK | R 5
OutPort_919121_2 | SOURCE | R 5
InPort_919154_0 | SINK | R 5
OutPort_919165_2 | SOURCE | R 5
InPort_1089962_1 | SINK | R 5
OutPort_919154_1 | SOURCE | R 5
InPort_919652_1 | SINK | R 5
OutPort_919154_2 | SOURCE | R 5
InPort_919521_2 | SINK | R 5
OutPort_919431_1 | SOURCE | R 5
InPort_919550_2 | SINK | R 5
OutPort_919536_0 | SOURCE | R 5
InPort_919121_2 | SINK | R 4
OutPort_919550_1 | SOURCE | R 4
InPort_919652_2 | SINK | R 5
OutPort_919560_1 | SOURCE | R 5
InPort_919154_2 | SINK | R 6
OutPort_919652_1 | SOURCE | R 6
InPort_919727_2 | SINK | R 5
OutPort_919662_1 | SOURCE | R 5
InPort_1065794_2 | SINK | R 5
OutPort_919727_1 | SOURCE | R 5
InPort_919771_0 | SINK | R 5
OutPort_925548_2 | SOURCE | R 5
Port_919771_1 | SOURCEANDSINK | R 5
Port_925463_1 | SOURCEANDSINK | R 5
InPort_925569_1 | SINK | R 5
OutPort_919771_2 | SOURCE | R 5
InPort_953096_2 | SINK | AE 26
OutPort_920542_0 | SOURCE | AE 26
InPort_920542_1 | SINK | AE 26
OutPort_951929_1 | SOURCE | AE 26
InPort_920542_5 | SINK | AE 2
OutPort_953073_1 | SOURCE | AE 2
InPort_920542_6 | SINK | AE 25
OutPort_953076_1 | SOURCE | AE 25
InPort_920542_7 | SINK | AE 25
OutPort_953079_1 | SOURCE | AE 25
InPort_923991_2 | SINK | AE 3
OutPort_920765_0 | SOURCE | AE 3
InPort_920765_1 | SINK | AE 3
OutPort_923993_1 | SOURCE | AE 3
InPort_920765_2 | SINK | AE 4
OutPort_923843_1 | SOURCE | AE 4
InPort_923993_2 | SINK | AE 3
OutPort_921120_0 | SOURCE | AE 3
InPort_921120_1 | SINK | AE 3
OutPort_1123822_1 | SOURCE | AE 3
InPort_921282_0 | SINK | AE 3
OutPort_923991_1 | SOURCE | AE 3
InPort_923890_2 | SINK | AE 3
OutPort_921282_1 | SOURCE | AE 3
InPort_1124097_1 | SINK | AE 3
OutPort_921282_2 | SOURCE | AE 3
InPort_1134094_1 | SINK | AE 23
OutPort_921361_0 | SOURCE | AE 23
InPort_921361_1 | SINK | AE 23
OutPort_1067885_4 | SOURCE | AE 23
Port_921439_1 | SOURCEANDSINK | AE 23
Port_924467_0 | SOURCEANDSINK | AE 23
Port_921443_0 | SOURCEANDSINK | AE 23
Port_921487_1 | SOURCEANDSINK | AE 23
InPort_921443_1 | SINK | AE 23
OutPort_924502_2 | SOURCE | AE 23
Port_921443_2 | SOURCEANDSINK | AE 23
Port_924307_1 | SOURCEANDSINK | AE 23
InPort_921562_0 | SINK | AE 23
OutPort_923647_1 | SOURCE | AE 23
InPort_922506_1 | SINK | AE 23
OutPort_921562_1 | SOURCE | AE 23
InPort_923647_2 | SINK | AE 23
OutPort_923649_1 | SOURCE | AE 23
InPort_923649_0 | SINK | AE 23
OutPort_924534_2 | SOURCE | AE 23
InPort_923757_1 | SINK | AE 3
OutPort_923843_2 | SOURCE | AE 3
InPort_923843_1 | SINK | AE 3
OutPort_920765_2 | SOURCE | AE 3
Port_923903_0 | SOURCEANDSINK | AE 3
Port_923936_1 | SOURCEANDSINK | AE 3
InPort_923903_1 | SINK | AE 3
OutPort_1124021_2 | SOURCE | AE 3
Port_923903_2 | SOURCEANDSINK | AE 3
Port_1124052_1 | SOURCEANDSINK | AE 3
InPort_924303_1 | SINK | AE 23
OutPort_924307_2 | SOURCE | AE 23
InPort_924307_1 | SINK | AE 23
OutPort_921443_2 | SOURCE | AE 23
InPort_924467_1 | SINK | AE 23
OutPort_1134094_2 | SOURCE | AE 23
InPort_924467_2 | SINK | AE 1
OutPort_924502_1 | SOURCE | AE 1
Port_924467_3 | SOURCEANDSINK | AE 1
Port_924534_1 | SOURCEANDSINK | AE 1
InPort_924502_1 | SINK | AE 23
OutPort_924467_2 | SOURCE | AE 23
InPort_924534_1 | SINK | AE 23
OutPort_924467_3 | SOURCE | AE 23
InPort_925216_1 | SINK | I 6
InPort_925227_2 | SINK | I 6
OutPort_1067636_0 | SOURCE | I 6
InPort_925420_0 | SINK | R 5
OutPort_1089963_2 | SOURCE | R 5
InPort_925548_1 | SINK | R 5
OutPort_925420_1 | SOURCE | R 5
InPort_925507_1 | SINK | R 5
OutPort_925569_2 | SOURCE | R 5
InPort_1088994_2 | SINK | AE 2
OutPort_925648_0 | SOURCE | AE 2
InPort_925648_1 | SINK | AE 2
OutPort_1089345_1 | SOURCE | AE 2
InPort_925648_7 | SINK | AE 2
OutPort_1088891_1 | SOURCE | AE 2
OutPort_936077_5 | SOURCE
Port_936077_6 | SOURCEANDSINK
Port_936077_7 | SOURCEANDSINK
Port_936077_8 | SOURCEANDSINK
InPort_944860_1 | SINK | AE 10
OutPort_946106_0 | SOURCE | AE 10
InPort_944867_1 | SINK | AE 11
OutPort_946171_0 | SOURCE | AE 11
Port_944923_1 | SOURCEANDSINK | AE 26
Port_952891_0 | SOURCEANDSINK | AE 26
InPort_944957_1 | SINK | AE 9
OutPort_945972_0 | SOURCE | AE 9
InPort_944984_1 | SINK | AE 8
OutPort_945715_0 | SOURCE | AE 8
InPort_945242_1 | SINK | AE 26
OutPort_945445_0 | SOURCE | AE 26
InPort_945249_1 | SINK | AE 6
OutPort_945538_0 | SOURCE | AE 6
InPort_945256_1 | SINK | AE 7
OutPort_945626_0 | SOURCE | AE 7
Port_945445_1 | SOURCEANDSINK | AE 26
Port_945499_1 | SOURCEANDSINK | AE 26
InPort_945445_2 | SINK | AE 5
OutPort_945519_1 | SOURCE | AE 5
InPort_945519_2 | SINK | AE 26
OutPort_946766_1 | SOURCE | AE 26
Port_945538_1 | SOURCEANDSINK | AE 6
Port_945585_1 | SOURCEANDSINK | AE 6
InPort_945538_2 | SINK | AE 6
OutPort_945939_1 | SOURCE | AE 6
Port_945626_1 | SOURCEANDSINK | AE 7
Port_945672_1 | SOURCEANDSINK | AE 7
InPort_945626_2 | SINK | AE 7
OutPort_945953_1 | SOURCE | AE 7
Port_945715_1 | SOURCEANDSINK | AE 8
Port_945748_1 | SOURCEANDSINK | AE 8
InPort_945715_2 | SINK | AE 8
OutPort_945865_1 | SOURCE | AE 8
InPort_945865_2 | SINK | AE 8
OutPort_946606_0 | SOURCE | AE 8
InPort_945939_2 | SINK | AE 6
OutPort_946816_0 | SOURCE | AE 6
InPort_945953_2 | SINK | AE 7
OutPort_946839_0 | SOURCE | AE 7
Port_945972_1 | SOURCEANDSINK | AE 9
Port_946046_1 | SOURCEANDSINK | AE 9
InPort_945972_2 | SINK | AE 9
OutPort_946087_1 | SOURCE | AE 9
InPort_946087_2 | SINK | AE 9
OutPort_946513_0 | SOURCE | AE 9
Port_946106_1 | SOURCEANDSINK | AE 10
Port_946144_1 | SOURCEANDSINK | AE 10
InPort_946106_2 | SINK | AE 10
OutPort_946153_1 | SOURCE | AE 10
InPort_946153_2 | SINK | AE 10
OutPort_946391_0 | SOURCE | AE 10
Port_946171_1 | SOURCEANDSINK | AE 11
Port_946206_1 | SOURCEANDSINK | AE 11
InPort_946171_2 | SINK | AE 11
OutPort_946215_1 | SOURCE | AE 11
InPort_946215_2 | SINK | AE 11
OutPort_946369_0 | SOURCE | AE 11
InPort_946267_0 | SINK | AE 26
OutPort_946703_1 | SOURCE | AE 26
InPort_953086_1 | SINK | AE 26
OutPort_946267_1 | SOURCE | AE 26
InPort_953091_1 | SINK | AE 26
OutPort_946267_7 | SOURCE | AE 26
InPort_953094_1 | SINK | AE 26
OutPort_946267_8 | SOURCE | AE 26
InPort_953098_1 | SINK | AE 26
OutPort_946267_9 | SOURCE | AE 26
InPort_1074594_1 | SINK | AE 26
OutPort_946267_10 | SOURCE | AE 26
InPort_946288_1 | SINK | AE 12
OutPort_946289_0 | SOURCE | AE 12
Port_946289_1 | SOURCEANDSINK | AE 12
Port_946290_1 | SOURCEANDSINK | AE 12
InPort_946289_2 | SINK | AE 12
OutPort_946291_1 | SOURCE | AE 12
InPort_946291_2 | SINK | AE 12
OutPort_946584_0 | SOURCE | AE 12
InPort_946358_1 | SINK | AE 26
OutPort_952891_4 | SOURCE | AE 26
InPort_946369_1 | SINK | I 9
OutPort_946358_2 | SOURCE | I 9
InPort_946381_1 | SINK | AE 26
OutPort_952891_3 | SOURCE | AE 26
InPort_946391_1 | SINK | I 10
OutPort_946381_2 | SOURCE | I 10
InPort_946513_1 | SINK | I 11
OutPort_1074594_2 | SOURCE | I 11
InPort_946584_1 | SINK | I 12
OutPort_953091_2 | SOURCE | I 12
InPort_946606_1 | SINK | I 13
OutPort_953094_2 | SOURCE | I 13
InPort_946703_2 | SINK | AE 26
OutPort_946671_0 | SOURCE | AE 26
InPort_946671_1 | SINK | AE 26
OutPort_953096_1 | SOURCE | AE 26
InPort_946766_0 | SINK | AE 26
OutPort_953073_2 | SOURCE | AE 26
InPort_946816_1 | SINK | I 15
OutPort_953076_2 | SOURCE | I 15
InPort_946839_1 | SINK | I 16
OutPort_953079_2 | SOURCE | I 16
InPort_947193_1 | SINK | R 3
OutPort_948295_5 | SOURCE
Port_948295_6 | SOURCEANDSINK
Port_948295_7 | SOURCEANDSINK
Port_948295_8 | SOURCEANDSINK
InPort_1071728_2 | SINK | AE 13
OutPort_949734_0 | SOURCE | AE 13
InPort_949734_1 | SINK | AE 13
OutPort_1084644_2 | SOURCE | AE 13
InPort_949734_3 | SINK | AE 13
OutPort_1071724_1 | SOURCE | AE 13
InPort_950659_1 | SINK | AE 14
OutPort_951087_0 | SOURCE | AE 14
Port_951087_1 | SOURCEANDSINK | AE 14
Port_951129_1 | SOURCEANDSINK | AE 14
InPort_951087_2 | SINK | AE 14
OutPort_951151_1 | SOURCE | AE 14
InPort_951151_2 | SINK | AE 14
OutPort_951180_1 | SOURCE | AE 14
InPort_951180_0 | SINK | I 17
OutPort_1088891_2 | SOURCE | I 17
InPort_951628_1 | SINK | AE 2
OutPort_951541_0 | SOURCE | AE 2
InPort_951541_1 | SINK | AE 2
OutPort_951554_2 | SOURCE | AE 2
InPort_951554_1 | SINK | AE 2
OutPort_951548_0 | SOURCE | AE 2
InPort_951548_1 | SINK | AE 2
OutPort_951720_1 | SOURCE | AE 2
InPort_951630_1 | SINK | AE 2
OutPort_951628_2 | SOURCE | AE 2
InPort_951662_1 | SINK | AE 2
OutPort_951630_0 | SOURCE | AE 2
InPort_951720_2 | SINK | AE 2
OutPort_951711_0 | SOURCE | AE 2
InPort_951711_1 | SINK | AE 2
OutPort_951755_1 | SOURCE | AE 2
InPort_951755_2 | SINK | AE 2
OutPort_1088938_0 | SOURCE | AE 2
InPort_951929_2 | SINK | AE 26
OutPort_951878_0 | SOURCE | AE 26
InPort_951878_1 | SINK | AE 26
OutPort_1089371_2 | SOURCE | AE 26
InPort_952135_1 | SINK | AE 15
OutPort_952181_0 | SOURCE | AE 15
Port_952181_1 | SOURCEANDSINK | AE 15
Port_952228_1 | SOURCEANDSINK | AE 15
InPort_952181_2 | SINK | AE 15
OutPort_952294_1 | SOURCE | AE 15
InPort_952294_2 | SINK | AE 15
OutPort_952361_1 | SOURCE | AE 15
InPort_952361_0 | SINK | I 18
OutPort_952969_2 | SOURCE | I 18
InPort_952421_1 | SINK | AE 16
OutPort_952469_0 | SOURCE | AE 16
Port_952469_1 | SOURCEANDSINK | AE 16
Port_952517_1 | SOURCEANDSINK | AE 16
InPort_952469_2 | SINK | AE 16
OutPort_952555_1 | SOURCE | AE 16
InPort_952555_2 | SINK | AE 16
OutPort_952625_1 | SOURCE | AE 16
InPort_952625_0 | SINK | I 19
OutPort_953098_2 | SOURCE | I 19
InPort_952891_1 | SINK | AE 26
OutPort_952998_1 | SOURCE | AE 26
InPort_952891_3 | SINK | AE 2
OutPort_946381_1 | SOURCE | AE 2
InPort_952962_0 | SINK | AE 26
OutPort_953086_2 | SOURCE | AE 26
InPort_952998_2 | SINK | AE 26
OutPort_952962_1 | SOURCE | AE 26
InPort_952969_1 | SINK | AE 26
OutPort_952962_3 | SOURCE | AE 26
InPort_953073_1 | SINK | AE 26
OutPort_920542_5 | SOURCE | AE 26
InPort_953076_1 | SINK | AE 26
OutPort_920542_6 | SOURCE | AE 26
InPort_953079_1 | SINK | AE 26
OutPort_920542_7 | SOURCE | AE 26
InPort_1062948_1 | SINK | AE 18
OutPort_1067355_0 | SOURCE | AE 18
InPort_1127170_1 | SINK | EX 1
OutPort_1062948_2 | SOURCE | EX 1
InPort_1063103_1 | SINK | AE 19
OutPort_1067405_0 | SOURCE | AE 19
InPort_1127606_1 | SINK | EX 9
OutPort_1063103_2 | SOURCE | EX 9
InPort_1063111_1 | SINK | AE 20
OutPort_1067442_0 | SOURCE | AE 20
InPort_1063996_1 | SINK | EX 8
OutPort_1063111_2 | SOURCE | EX 8
InPort_1063151_1 | SINK | AE 21
OutPort_1067473_0 | SOURCE | AE 21
InPort_1092790_1 | SINK | EX 3
OutPort_1063151_2 | SOURCE | EX 3
InPort_1064072_1 | SINK | AE 22
OutPort_1067542_0 | SOURCE | AE 22
InPort_1126103_1 | SINK | EX 2
OutPort_1064072_2 | SOURCE | EX 2
InPort_1064215_2 | SINK | EX 2
OutPort_1126083_0 | SOURCE | EX 2
InPort_1064336_2 | SINK | EX 3
OutPort_1064325_0 | SOURCE | EX 3
InPort_1064325_1 | SINK | EX 3
OutPort_1064394_1 | SOURCE | EX 3
InPort_1064394_2 | SINK | EX 3
OutPort_1064339_0 | SOURCE | EX 3
InPort_1064339_1 | SINK | EX 3
OutPort_1092790_0 | SOURCE | EX 3
InPort_1065355_1 | SINK | AE 13
OutPort_1066529_1 | SOURCE | AE 13
InPort_1071531_1 | SINK | AE 13
OutPort_1065626_0 | SOURCE | AE 13
InPort_1065626_1 | SINK | AE 13
OutPort_1071493_1 | SOURCE | AE 13
InPort_1066592_1 | SINK | AE 13
OutPort_1065637_0 | SOURCE | AE 13
InPort_1065637_1 | SINK | AE 13
OutPort_1065685_1 | SOURCE | AE 13
InPort_1065685_2 | SINK | AE 13
OutPort_1065657_0 | SOURCE | AE 13
InPort_1065657_1 | SINK | AE 13
OutPort_1071728_1 | SOURCE | AE 13
InPort_1065794_0 | SINK | R 5
OutPort_1089962_2 | SOURCE | R 5
InPort_1089963_1 | SINK | R 5
OutPort_1065794_1 | SOURCE | R 5
InPort_919727_1 | SINK | R 5
OutPort_1065794_2 | SOURCE | R 5
InPort_1065997_1 | SINK | AE 17
OutPort_1066105_0 | SOURCE | AE 17
Port_1066105_1 | SOURCEANDSINK | AE 17
Port_1066203_1 | SOURCEANDSINK | AE 17
InPort_1066105_2 | SINK | AE 17
OutPort_1066224_1 | SOURCE | AE 17
InPort_1066224_2 | SINK | AE 17
OutPort_1066909_0 | SOURCE | AE 17
InPort_1066529_0 | SINK | AE 13
OutPort_1071724_2 | SOURCE | AE 13
InPort_1066695_0 | SINK | AE 13
OutPort_1066592_2 | SOURCE | AE 13
InPort_1071493_2 | SINK | AE 13
OutPort_1066695_1 | SOURCE | AE 13
InPort_1071400_1 | SINK | AE 13
OutPort_1066695_6 | SOURCE | AE 13
InPort_1071443_1 | SINK | AE 13
OutPort_1066695_7 | SOURCE | AE 13
InPort_1066880_1 | SINK | AE 13
OutPort_1071533_0 | SOURCE | AE 13
InPort_1066909_1 | SINK | I 20
OutPort_1071400_2 | SOURCE | I 20
InPort_1067355_1 | SINK | AE 18
InPort_1067405_1 | SINK | AE 19
InPort_1067442_1 | SINK | AE 20
InPort_1067473_1 | SINK | AE 21
InPort_1067542_1 | SINK | AE 22
InPort_1067885_2 | SINK | AE 23
OutPort_1067839_0 | SOURCE | AE 23
InPort_1067839_1 | SINK | AE 23
OutPort_1068256_1 | SOURCE | AE 23
InPort_1123839_1 | SINK | AE 23
OutPort_1067885_3 | SOURCE | AE 23
Port_1068002_1 | SOURCEANDSINK | AE 3
Port_1068002_2 | SOURCEANDSINK | AE 3
InPort_1068256_2 | SINK | AE 23
OutPort_1068259_0 | SOURCE | AE 23
InPort_1068259_1 | SINK | AE 23
OutPort_1068305_1 | SOURCE | AE 23
InPort_1068305_2 | SINK | AE 23
OutPort_1068298_0 | SOURCE | AE 23
InPort_1068298_1 | SINK | AE 23
OutPort_1086273_1 | SOURCE | AE 23
InPort_1068298_2 | SINK | AE 23
OutPort_1123793_1 | SOURCE | AE 23
InPort_1068452_1 | SINK | R 1
OutPort_1068402_1 | SOURCE | R 1
InPort_1068442_0 | SINK | R 1
OutPort_1068452_2 | SOURCE | R 1
InPort_1068477_1 | SINK | R 1
OutPort_1068442_1 | SOURCE | R 1
Port_1068606_0 | SOURCEANDSINK | R 1
Port_1068689_2 | SOURCEANDSINK | R 1
Port_1068606_1 | SOURCEANDSINK | R 1
Port_1068713_1 | SOURCEANDSINK | R 1
Port_1068740_0 | SOURCEANDSINK | R 2
Port_1068935_1 | SOURCEANDSINK | R 2
Port_1068740_1 | SOURCEANDSINK | R 2
Port_1068955_2 | SOURCEANDSINK | R 2
InPort_1068853_0 | SINK | R 2
OutPort_1068906_2 | SOURCE | R 2
InPort_1068916_1 | SINK | R 2
OutPort_1068853_1 | SOURCE | R 2
InPort_1068909_0 | SINK | R 2
OutPort_1068916_2 | SOURCE | R 2
InPort_1068927_1 | SINK | R 2
OutPort_1068909_1 | SOURCE | R 2
InPort_1068919_1 | SINK | R 2
OutPort_1068927_2 | SOURCE | R 2
InPort_1069948_1 | SINK | AE 23
OutPort_1070180_0 | SOURCE | AE 23
Port_1070058_0 | SOURCEANDSINK | AE 23
Port_1070157_1 | SOURCEANDSINK | AE 23
InPort_1070058_1 | SINK | AE 23
OutPort_1123793_2 | SOURCE | AE 23
Port_1070058_2 | SOURCEANDSINK | AE 23
Port_1070188_1 | SOURCEANDSINK | AE 23
InPort_1070180_1 | SINK | AE 23
OutPort_1070188_2 | SOURCE | AE 23
InPort_1070188_1 | SINK | AE 23
OutPort_1070058_2 | SOURCE | AE 23
InPort_1084644_1 | SINK | AE 13
OutPort_1070331_0 | SOURCE | AE 13
InPort_1070331_1 | SINK | AE 13
OutPort_1084756_1 | SOURCE | AE 13
InPort_1070781_0 | SINK | AE 13
OutPort_1071443_2 | SOURCE | AE 13
InPort_1070795_2 | SINK | AE 13
OutPort_1070781_1 | SOURCE | AE 13
InPort_1070788_0 | SINK | AE 13
OutPort_1070795_1 | SOURCE | AE 13
InPort_1070921_1 | SINK | AE 13
OutPort_1070788_1 | SOURCE | AE 13
InPort_1070914_0 | SINK | AE 13
OutPort_1070921_2 | SOURCE | AE 13
InPort_1071593_1 | SINK | AE 13
OutPort_1070914_1 | SOURCE | AE 13
InPort_1070924_0 | SINK | AE 13
OutPort_1071593_2 | SOURCE | AE 13
InPort_1071595_1 | SINK | AE 13
OutPort_1070924_1 | SOURCE | AE 13
InPort_1070992_1 | SINK | AE 13
OutPort_1071588_0 | SOURCE | AE 13
InPort_1071533_1 | SINK | AE 13
OutPort_1071531_2 | SOURCE | AE 13
InPort_1071588_1 | SINK | AE 13
OutPort_1071595_2 | SOURCE | AE 13
InPort_1071724_1 | SINK | AE 13
OutPort_949734_3 | SOURCE | AE 13
Port_1072802_0 | SOURCEANDSINK | I 5
Port_1072970_1 | SOURCEANDSINK | I 5
Port_1072892_2 | SOURCEANDSINK | I 5
Port_1073011_0 | SOURCEANDSINK | I 5
Port_1081998_1 | SOURCEANDSINK
InPort_1084711_0 | SINK | AE 13
OutPort_1084501_1 | SOURCE | AE 13
InPort_1084501_2 | SINK | AE 24
OutPort_1084771_0 | SOURCE | AE 24
InPort_1084756_2 | SINK | AE 13
OutPort_1084572_0 | SOURCE | AE 13
InPort_1084771_0 | SINK | AE 24
OutPort_1084501_2 | SOURCE | AE 24
InPort_1086007_1 | SINK | AE 24
OutPort_1084771_1 | SOURCE | AE 24
InPort_1085687_1 | SINK | AE 24
OutPort_1084845_0 | SOURCE | AE 24
InPort_1084845_1 | SINK | AE 24
OutPort_1086007_2 | SOURCE | AE 24
InPort_1086273_2 | SINK | AE 23
OutPort_1086264_0 | SOURCE | AE 23
InPort_1086264_1 | SINK | AE 23
OutPort_1086299_1 | SOURCE | AE 23
InPort_1086299_2 | SINK | AE 23
OutPort_1088115_0 | SOURCE | AE 23
InPort_1088206_2 | SINK | AE 23
OutPort_1087751_2 | SOURCE | AE 23
Port_1087751_3 | SOURCEANDSINK | AE 23
InPort_1088115_1 | SINK | AE 23
OutPort_1088137_1 | SOURCE | AE 23
InPort_1088137_2 | SINK | AE 23
OutPort_1088122_0 | SOURCE | AE 23
InPort_1088122_1 | SINK | AE 23
OutPort_1088204_1 | SOURCE | AE 23
InPort_1088204_2 | SINK | AE 23
OutPort_1088140_0 | SOURCE | AE 23
InPort_1088140_1 | SINK | AE 23
OutPort_1088206_1 | SOURCE | AE 23
InPort_1089595_0 | SINK | AE 26
OutPort_1088407_2 | SOURCE | AE 26
Port_1088407_3 | SOURCEANDSINK | AE 26
InPort_1088891_1 | SINK | AE 2
OutPort_925648_7 | SOURCE | AE 2
InPort_1088938_1 | SINK | AE 2
OutPort_1088993_1 | SOURCE | AE 2
InPort_1088993_2 | SINK | AE 2
OutPort_1088944_0 | SOURCE | AE 2
InPort_1088944_1 | SINK | AE 2
OutPort_1088994_1 | SOURCE | AE 2
InPort_1089371_1 | SINK | AE 26
OutPort_1089078_0 | SOURCE | AE 26
InPort_1089078_1 | SINK | AE 26
OutPort_1089253_4 | SOURCE | AE 26
InPort_1089253_2 | SINK | AE 26
OutPort_1089197_0 | SOURCE | AE 26
InPort_1089197_1 | SINK | AE 26
OutPort_1089567_1 | SOURCE | AE 26
InPort_1089317_0 | SINK | AE 26
OutPort_1089253_3 | SOURCE | AE 26
InPort_1089345_2 | SINK | AE 2
OutPort_1089317_1 | SOURCE | AE 2
InPort_1089567_2 | SINK | AE 26
OutPort_1089403_0 | SOURCE | AE 26
InPort_1089403_1 | SINK | AE 26
OutPort_1089699_1 | SOURCE | AE 26
InPort_1089611_2 | SINK | AE 26
OutPort_1089595_1 | SOURCE | AE 26
InPort_1089604_0 | SINK | AE 26
OutPort_1089611_1 | SOURCE | AE 26
InPort_1089701_2 | SINK | AE 26
OutPort_1089604_1 | SOURCE | AE 26
InPort_1089699_2 | SINK | AE 26
OutPort_1089648_0 | SOURCE | AE 26
InPort_1089648_1 | SINK | AE 26
OutPort_1089701_1 | SOURCE | AE 26
Port_1095715_1 | SOURCEANDSINK | I 8
InPort_1095808_2 | SINK | I 8
OutPort_1095771_0 | SOURCE | I 8
InPort_1095771_1 | SINK | I 8
InPort_1112884_2 | SINK | EX 11
OutPort_1113724_0 | SOURCE | EX 11
InPort_1113724_1 | SINK | EX 11
OutPort_1113840_2 | SOURCE | EX 11
InPort_1113831_0 | SINK | EX 11
OutPort_1113888_1 | SOURCE | EX 11
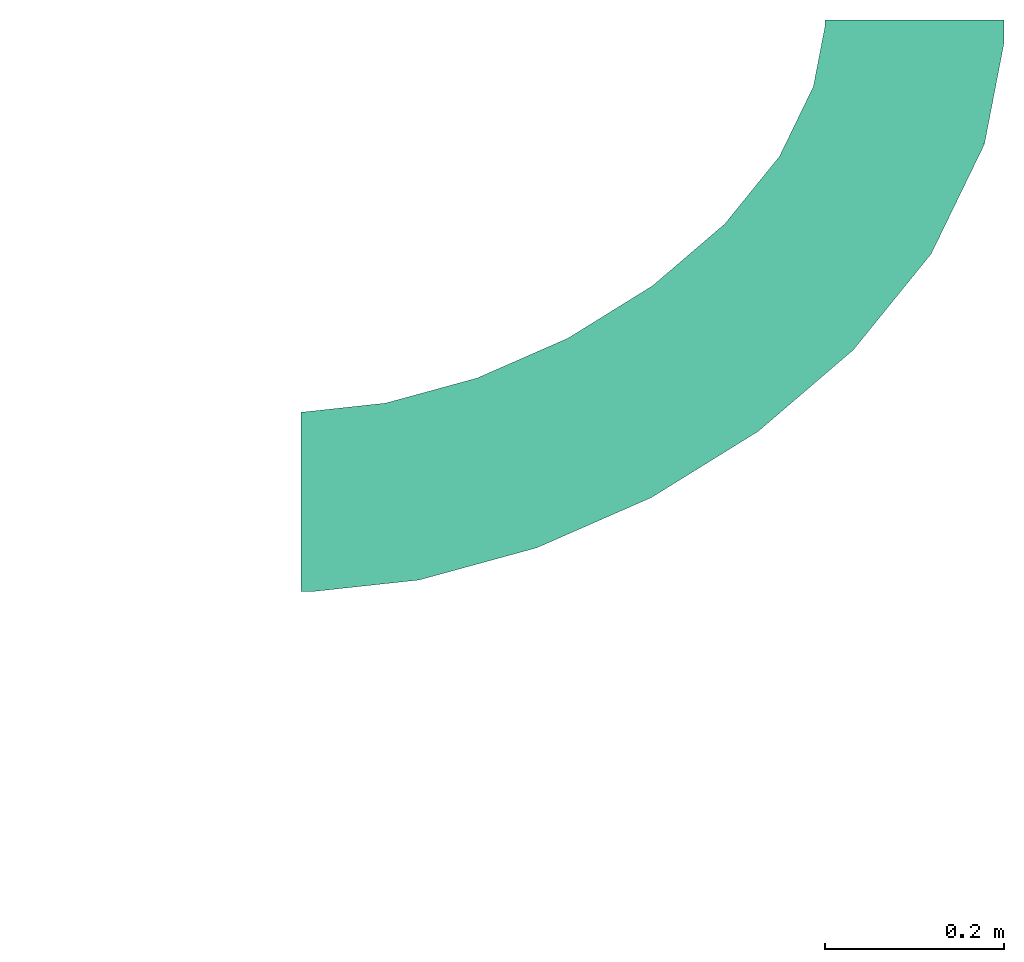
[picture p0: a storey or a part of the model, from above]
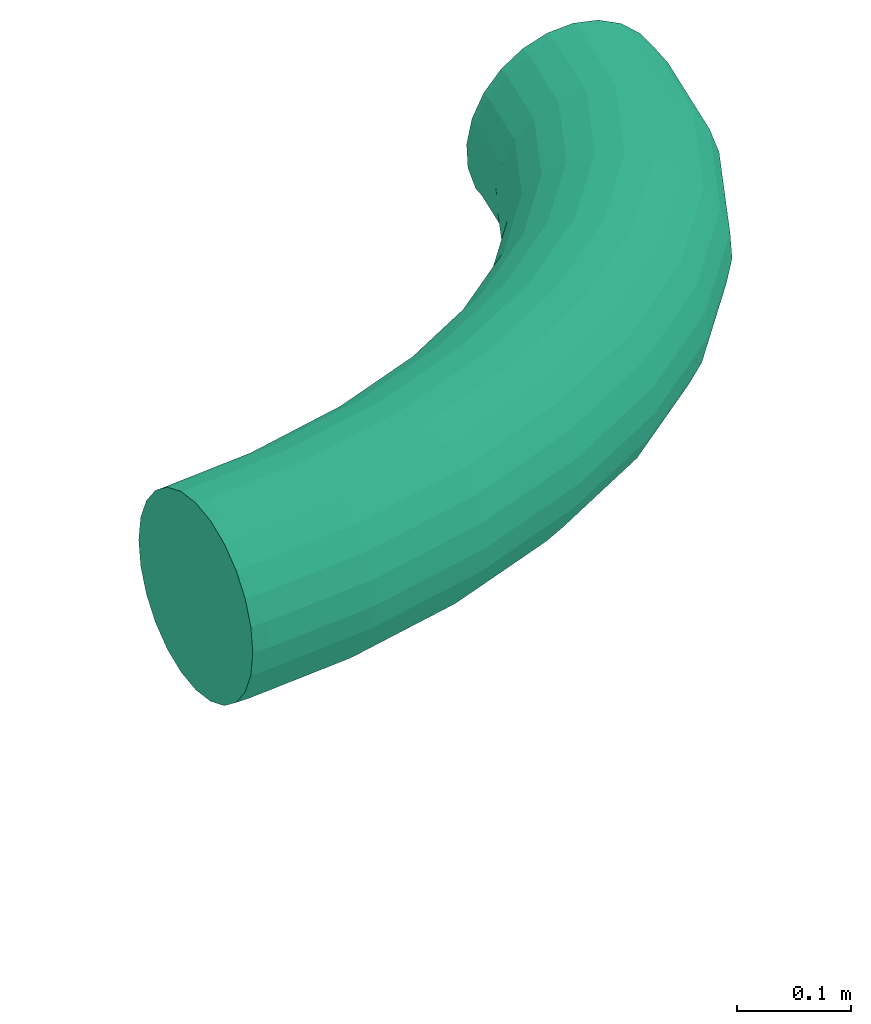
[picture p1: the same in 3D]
Properties of the parts of a building model (IFC2X3), part 2 of 2

# IfcDistributionPort (1531)
Name | FlowDirection | Group
Port_1113831_1 | SOURCEANDSINK | EX 11
Port_1113866_1 | SOURCEANDSINK | EX 11
InPort_1113840_1 | SINK | EX 11
OutPort_1113831_2 | SOURCE | EX 11
InPort_1113888_2 | SINK | EX 11
OutPort_1113881_0 | SOURCE | EX 11
InPort_1113881_1 | SINK | EX 11
OutPort_1113960_1 | SOURCE | EX 11
InPort_1113960_2 | SINK | EX 11
OutPort_1113951_0 | SOURCE | EX 11
InPort_1113951_1 | SINK | EX 11
OutPort_1114233_1 | SOURCE | EX 11
InPort_1114233_2 | SINK | EX 11
OutPort_1113963_0 | SOURCE | EX 11
InPort_1113963_1 | SINK | EX 11
OutPort_1114369_0 | SOURCE | EX 11
InPort_1114082_1 | SINK | EX 10
OutPort_1114521_0 | SOURCE | EX 10
InPort_1114369_1 | SINK | EX 11
OutPort_1114082_2 | SOURCE | EX 11
InPort_1114521_1 | SINK | EX 10
InPort_1119958_0 | SINK | I 8
OutPort_1120141_2 | SOURCE | I 8
InPort_1120182_2 | SINK | I 8
OutPort_1119958_1 | SOURCE | I 8
InPort_1123793_1 | SINK | AE 23
OutPort_1068298_2 | SOURCE | AE 23
InPort_1123822_2 | SINK | AE 3
OutPort_1123811_0 | SOURCE | AE 3
InPort_1123811_1 | SINK | AE 3
OutPort_1123895_1 | SOURCE | AE 3
InPort_1123811_2 | SINK | AE 3
OutPort_1124021_1 | SOURCE | AE 3
InPort_1123895_2 | SINK | AE 3
OutPort_1123839_0 | SOURCE | AE 3
InPort_1124021_1 | SINK | AE 3
OutPort_1123811_2 | SOURCE | AE 3
InPort_1124044_1 | SINK | AE 3
OutPort_1124052_2 | SOURCE | AE 3
InPort_1124052_1 | SINK | AE 3
OutPort_923903_2 | SOURCE | AE 3
InPort_1124093_1 | SINK | AE 3
OutPort_1124097_2 | SOURCE | AE 3
InPort_1126083_1 | SINK | EX 2
OutPort_1126104_1 | SOURCE | EX 2
InPort_1126090_0 | SINK | EX 2
OutPort_1126103_0 | SOURCE | EX 2
InPort_1126104_2 | SINK | EX 2
OutPort_1126090_1 | SOURCE | EX 2
InPort_1127053_1 | SINK | EX 1
OutPort_1127062_2 | SOURCE | EX 1
InPort_1127062_1 | SINK | EX 1
OutPort_908865_2 | SOURCE | EX 1
InPort_1127072_1 | SINK | EX 1
OutPort_1127080_2 | SOURCE | EX 1
InPort_1127080_1 | SINK | EX 1
OutPort_908659_2 | SOURCE | EX 1
InPort_1127089_1 | SINK | EX 1
OutPort_1127095_2 | SOURCE | EX 1
InPort_1127409_2 | SINK | EX 8
OutPort_1127271_0 | SOURCE | EX 8
InPort_1127271_1 | SINK | EX 8
OutPort_1127426_1 | SOURCE | EX 8
InPort_1127336_2 | SINK | EX 9
OutPort_1127545_0 | SOURCE | EX 9
InPort_1127416_0 | SINK | EX 8
OutPort_1127386_2 | SOURCE | EX 8
InPort_1127426_2 | SINK | EX 8
OutPort_1127416_1 | SOURCE | EX 8
InPort_1127545_1 | SINK | EX 9
OutPort_1127623_2 | SOURCE | EX 9
InPort_1127624_0 | SINK | EX 9
OutPort_1127606_0 | SOURCE | EX 9
InPort_1127623_1 | SINK | EX 9
OutPort_1127614_0 | SOURCE | EX 9
InPort_1127614_1 | SINK | EX 9
OutPort_1127630_1 | SOURCE | EX 9
InPort_1127630_2 | SINK | EX 9
OutPort_1127624_1 | SOURCE | EX 9
InPort_1129495_1 | SINK | EX 9
OutPort_909766_3 | SOURCE | EX 9
InPort_1134556_1 | SINK | I 8
OutPort_913974_2 | SOURCE | I 8
InPort_1134591_1 | SINK | I 8
OutPort_913974_3 | SOURCE | I 8

# IfcFlowFitting: BTS vanes:1 Splitter Vanes (87)
Type - Material: <Unnamed>
Pset_DistributionFlowElementCommon - Reference: 1 Splitter Vanes; sets with these values: 2
Name (BTS vanes:1 Splitter Vanes:...) | In | Group
837863 | LAJE TÉCNICA | I 1
837886 | LAJE TÉCNICA | I 1
838440 | LAJE TÉCNICA | I 1
838456 | LAJE TÉCNICA | I 1
838585 | LAJE TÉCNICA | Mecânica Ar de fornecimento 1
838589 | LAJE TÉCNICA | Mecânica Ar de fornecimento 1
838590 | LAJE TÉCNICA | Mecânica Ar de fornecimento 1
873376 | LAJE TÉCNICA | Mecânica Ar de fornecimento 1
874760 | LAJE TÉCNICA | Mecânica Ar de fornecimento 1
874805 | LAJE TÉCNICA | Mecânica Ar de fornecimento 1
874873 | LAJE TÉCNICA | I 1
874880 | LAJE TÉCNICA | I 1
875036 | LAJE TÉCNICA | I 1
875070 | LAJE TÉCNICA | I 1
875174 | LAJE TÉCNICA | Mecânica Ar de fornecimento 1
875176 | 1PAV | Mecânica Ar de fornecimento 1
878363 | LAJE TÉCNICA | R 2
878412 | LAJE TÉCNICA | R 2
878438 | 2PAV | R 1
878444 | LAJE TÉCNICA | R 1
878476 | LAJE TÉCNICA | R 1
878595 | LAJE TÉCNICA | R 2
878823 | LAJE TÉCNICA | R 2
878857 | LAJE TÉCNICA | R 1
903880 | 2PAV | I 6
903886 | 2PAV | I 6
906587 | 1PAV | EX 2
906595 | 1PAV | EX 2
906759 | TÉRREO +0.32m | EX 2
907081 | 1PAV | EX 2
909076 | TÉRREO +0.32m | EX 8
910186 | 2PAV | EX 9
910574 | TÉRREO +0.32m | EX 1
910586 | TÉRREO +0.32m | EX 1
910595 | TÉRREO +0.32m | EX 1
911679 | TÉRREO +0.32m | EX 3
911886 | TÉRREO +0.32m | EX 2
911896 | TÉRREO +0.32m | EX 2
923993 | TÉRREO +0.32m | AE 3
946703 | 2PAV | AE 26
951554 | 2PAV | AE 2
951720 | 2PAV | AE 2
951755 | 2PAV | AE 2
951929 | 2PAV | AE 26
1064215 | TÉRREO +0.32m | EX 2
1064322 | TÉRREO +0.32m | EX 3
1064336 | TÉRREO +0.32m | EX 3
1064394 | TÉRREO +0.32m | EX 3
1065685 | 1PAV | AE 13
1066592 | 1PAV | AE 13
1068002 | TÉRREO +0.32m | AE 3
1068256 | TÉRREO +0.32m | AE 23
1068452 | LAJE TÉCNICA | R 1
1068476 | LAJE TÉCNICA | R 1
1068477 | LAJE TÉCNICA | R 1
1068906 | LAJE TÉCNICA | R 2
1068916 | LAJE TÉCNICA | R 2
1068927 | LAJE TÉCNICA | R 2
1070795 | 1PAV | AE 13
1070921 | 1PAV | AE 13
1071593 | 1PAV | AE 13
1084644 | 1PAV | AE 13
1086273 | TÉRREO +0.32m | AE 23
1086299 | TÉRREO +0.32m | AE 23
1088137 | LAJE TÉCNICA | AE 23
1088204 | LAJE TÉCNICA | AE 23
1088993 | 2PAV | AE 2
1089345 | 2PAV | AE 2
1089371 | 2PAV | AE 26
1089567 | 2PAV | AE 26
1089611 | LAJE TÉCNICA | AE 26
1089699 | 2PAV | AE 26
1089963 | 2PAV | R 5
1113888 | TÉRREO +0.32m | EX 11
1113960 | TÉRREO +0.32m | EX 11
1114233 | TÉRREO +0.32m | EX 11
1123895 | TÉRREO +0.32m | AE 3
1126104 | LAJE TÉCNICA | EX 2
1127168 | TÉRREO +0.32m | EX 1
1127336 | 2PAV | EX 9
1127370 | LAJE TÉCNICA | EX 8
1127386 | TÉRREO +0.32m | EX 8
1127409 | TÉRREO +0.32m | EX 8
1127426 | TÉRREO +0.32m | EX 8
1127623 | LAJE TÉCNICA | EX 9
1127630 | LAJE TÉCNICA | EX 9
1134094 | TÉRREO +0.32m | AE 23

# IfcFlowFitting: M_Encaixe de duto redondo:Padrão (48)
Type - Material: <Unnamed>
Pset_DistributionFlowElementCommon - Reference: Padrão; sets with these values: 2
Name (M_Encaixe de duto redondo:Padrão:...) | In | Group
819832 | 2PAV | Mecânica Ar de fornecimento 1; I 2
819874 | 2PAV | Mecânica Ar de fornecimento 1; I 2
820118 | 2PAV | I 1; I 3
820128 | 2PAV | I 1; I 3
873420 | 2PAV | Mecânica Ar de fornecimento 1
873423 | 2PAV | Mecânica Ar de fornecimento 1
873444 | 2PAV | Mecânica Ar de fornecimento 1
873447 | 2PAV | Mecânica Ar de fornecimento 1
873459 | 2PAV | Mecânica Ar de fornecimento 1
873462 | 2PAV | Mecânica Ar de fornecimento 1
873503 | 2PAV | I 1
873505 | 2PAV | I 1
874404 | LAJE TÉCNICA | I 1
874430 | LAJE TÉCNICA | I 1
876085 | LAJE TÉCNICA | Mecânica Ar de fornecimento 1
876095 | LAJE TÉCNICA | Mecânica Ar de fornecimento 1
876241 | LAJE TÉCNICA | I 1
876275 | LAJE TÉCNICA | I 1
876320 | LAJE TÉCNICA | I 1
876328 | LAJE TÉCNICA | I 1
945519 | 2PAV | AE 26; AE 5
945865 | 2PAV | AE 8
945939 | 2PAV | AE 6
945953 | 2PAV | AE 7
946087 | 2PAV | AE 9
946153 | 2PAV | AE 10
946215 | 2PAV | AE 11
946291 | 2PAV | AE 12
946358 | 2PAV | AE 26; I 9
946381 | 2PAV | AE 26; AE 2; I 10
951151 | 2PAV | AE 14
952294 | 2PAV | AE 15
952555 | 2PAV | AE 16
952969 | 2PAV | AE 26; I 18
953073 | 2PAV | AE 26; AE 2
953076 | 2PAV | AE 26; AE 25; I 15
953079 | 2PAV | AE 26; AE 25; I 16
953091 | 2PAV | AE 26; I 12
953094 | 2PAV | AE 26; I 13
953098 | 2PAV | AE 26; I 19
1066224 | TÉRREO +0.32m | AE 17
1071400 | 1PAV | AE 13; I 20
1074594 | 1PAV | AE 26; I 11
1088891 | 2PAV | AE 2; I 17
1134556 | LAJE TÉCNICA | I 8
1134591 | LAJE TÉCNICA | I 8
1134652 | LAJE TÉCNICA | I 8
1134660 | LAJE TÉCNICA | I 8

# IfcFlowFitting: M_Rectangular Tap - Beveled:Standard (50)
Type - Material: <Unnamed>
Pset_DistributionFlowElementCommon - Reference: Standard; sets with these values: 2
Name (M_Rectangular Tap - Beveled:Standard:...) | In | Group
833259 | 2PAV | R 1
833279 | 2PAV | R 1
833294 | 2PAV | R 1
833305 | 2PAV | R 1
833323 | 2PAV | R 2
833333 | 2PAV | R 2
833342 | 2PAV | R 2
833351 | 2PAV | R 2
895366 | 1PAV | I 5
895404 | 1PAV | I 5
895437 | 1PAV | I 5
895468 | 1PAV | I 5
895501 | 1PAV | I 5
907079 | 1PAV | EX 2; EX 5
907281 | 2PAV | EX 2
909431 | TÉRREO +0.32m | EX 8
909597 | TÉRREO +0.32m | EX 8
909977 | 2PAV | EX 9
910147 | 2PAV | EX 9
910805 | 2PAV | I 6
910890 | 2PAV | I 6; I 4
910975 | 2PAV | I 6; I 7
911044 | 2PAV | I 6
911653 | 2PAV | EX 3
912506 | 1PAV | EX 2
919521 | 2PAV | R 5
919550 | 2PAV | R 5; R 4
919652 | 2PAV | R 5; R 6
919727 | 2PAV | R 5
923843 | TÉRREO +0.32m | AE 3; AE 4
924307 | TÉRREO +0.32m | AE 23
924502 | TÉRREO +0.32m | AE 23; AE 1
924534 | TÉRREO +0.32m | AE 23; AE 1
925569 | 2PAV | R 5
1068689 | LAJE TÉCNICA | R 1
1068955 | LAJE TÉCNICA | R 2
1070188 | 1PAV | AE 23
1071443 | 1PAV | AE 13
1071724 | 1PAV | AE 13
1072892 | 1PAV | I 5
1113840 | TÉRREO +0.32m | EX 11
1123793 | 1PAV | AE 23
1124021 | TÉRREO +0.32m | AE 3
1124052 | TÉRREO +0.32m | AE 3
1124097 | TÉRREO +0.32m | AE 3
1125579 | 1PAV | EX 2
1127062 | TÉRREO +0.32m | EX 1
1127080 | TÉRREO +0.32m | EX 1
1127095 | TÉRREO +0.32m | EX 1
1129495 | 2PAV | EX 9

# IfcFlowFitting: M_Rectangular Transition - L:150 mm (L), M_Rectangular Transition - L:150 mm (L):912508
In: 1PAV
Type - Material: <Unnamed>
Pset_DistributionFlowElementCommon - Reference: 150 mm (L); sets with these values: 2
Group: EX 2

# IfcFlowFitting: M_Rectangular Transition - L:250 mm (L) (5)
Type - Material: <Unnamed>
Pset_DistributionFlowElementCommon - Reference: 250 mm (L); sets with these values: 2
Name (M_Rectangular Transition - L:250 mm (L):...) | In | Group
1088206 | LAJE TÉCNICA | AE 23
1088994 | 2PAV | AE 2
1089701 | 2PAV | AE 26
1120141 | TÉRREO +0.32m | I 8
1120182 | TÉRREO +0.32m | I 8

# IfcFlowFitting: M_Rectangular Transition - L:400 mm (L) (43)
Type - Material: <Unnamed>
Pset_DistributionFlowElementCommon - Reference: 400 mm (L); sets with these values: 2
Name (M_Rectangular Transition - L:400 mm (L):...) | In | Group
831641 | 2PAV | R 2
831686 | 2PAV | R 2
831687 | 2PAV | R 2
831728 | 2PAV | R 1
831748 | 2PAV | R 1
831749 | 2PAV | R 1
873441 | 2PAV | Mecânica Ar de fornecimento 1
873442 | 2PAV | Mecânica Ar de fornecimento 1
873457 | 2PAV | Mecânica Ar de fornecimento 1
873502 | 2PAV | I 1
873513 | 2PAV | I 1
873514 | 2PAV | I 1
873556 | 2PAV | I 1
874549 | 2PAV | Mecânica Ar de fornecimento 1
902816 | 2PAV | I 6
902839 | 2PAV | I 6
902858 | 2PAV | I 6
906836 | TÉRREO +0.32m | EX 2
907222 | TÉRREO +0.32m | EX 2
908670 | TÉRREO +0.32m | EX 1
908695 | TÉRREO +0.32m | EX 1
909034 | TÉRREO +0.32m | EX 8
911681 | TÉRREO +0.32m | EX 3
919132 | 2PAV | R 5
919165 | 2PAV | R 5
923890 | TÉRREO +0.32m | AE 3
923991 | TÉRREO +0.32m | AE 3
925227 | 2PAV | I 6
925548 | 2PAV | R 5
952998 | 2PAV | AE 26
953086 | 2PAV | AE 26
953096 | 2PAV | AE 26
1068305 | TÉRREO +0.32m | AE 23
1071493 | 1PAV | AE 13
1071595 | 1PAV | AE 13
1071728 | 1PAV | AE 13
1084756 | 1PAV | AE 13
1086007 | 1PAV | AE 24
1089962 | 2PAV | R 5
1095808 | TÉRREO +0.32m | I 8
1123822 | TÉRREO +0.32m | AE 3
1129736 | 2PAV | EX 9
1129737 | 2PAV | EX 9

# IfcFlowFitting: M_Rectangular Transition - Length x2:250+100, M_Rectangular Transition - Length x2:250+100:1067885
In: TÉRREO +0.32m
Type - Material: <Unnamed>
Pset_DistributionFlowElementCommon - Reference: 250+100; sets with these values: 2
Group: AE 23

# IfcFlowFitting: M_Rectangular Transition - Length x2:300+125, M_Rectangular Transition - Length x2:300+125:1089253
In: 2PAV
Type - Material: <Unnamed>
Pset_DistributionFlowElementCommon - Reference: 300+125; sets with these values: 2
Group: AE 26

# IfcFlowFitting: M_Rectangular Transition - Length x2:515+515 (2)
In: 1PAV
Type - Material: <Unnamed>
Pset_DistributionFlowElementCommon - Reference: 515+515; sets with these values: 2
Name (M_Rectangular Transition - Length x2:515+515:...) | Group
838350 | I 1
838588 | Mecânica Ar de fornecimento 1

# IfcFlowFitting: M_Tampa retangular:Padrão (36)
Type - Material: <Unnamed>
Pset_DistributionFlowElementCommon - Reference: Padrão; sets with these values: 2
Name (M_Tampa retangular:Padrão:...) | In | Group
833313 | 2PAV | R 1
833358 | 2PAV | R 2
874556 | 1PAV | Mecânica Ar de fornecimento 1
875441 | 1PAV | I 1
895529 | 1PAV | I 5
895570 | 1PAV | I 5
908977 | TÉRREO +0.32m | EX 1
909989 | 2PAV | EX 9
910560 | TÉRREO +0.32m | EX 8
911081 | 2PAV | I 6
914011 | TÉRREO +0.32m | I 8
918098 | TÉRREO +0.32m | R 3
919225 | 2PAV | R 5
921439 | TÉRREO +0.32m | AE 23
921487 | TÉRREO +0.32m | AE 23
923936 | TÉRREO +0.32m | AE 3
925463 | 2PAV | R 5
944923 | 2PAV | AE 26
945499 | 2PAV | AE 26
945585 | 2PAV | AE 6
945672 | 2PAV | AE 7
945748 | 2PAV | AE 8
946046 | 2PAV | AE 9
946144 | 2PAV | AE 10
946206 | 2PAV | AE 11
946290 | 2PAV | AE 12
951129 | 2PAV | AE 14
952228 | 2PAV | AE 15
952517 | 2PAV | AE 16
1066203 | TÉRREO +0.32m | AE 17
1068713 | LAJE TÉCNICA | R 1
1068935 | LAJE TÉCNICA | R 2
1070157 | 1PAV | AE 23
1072970 | 1PAV | I 5
1113866 | TÉRREO +0.32m | EX 11
1125596 | 1PAV | EX 2

# IfcFlowFitting: M_Transição retangular para oval - Ângulo:45 Graus (6)
Type - Material: <Unnamed>
Pset_DistributionFlowElementCommon - Reference: 45 Graus; sets with these values: 2
Name (M_Transição retangular para oval - Ângulo:45 Graus:...) | In | Group
1063996 | LAJE TÉCNICA | EX 8
1092790 | TÉRREO +0.32m | EX 3
1114369 | TÉRREO +0.32m | EX 11
1126103 | LAJE TÉCNICA | EX 2
1127170 | TÉRREO +0.32m | EX 1
1127606 | LAJE TÉCNICA | EX 9

# IfcFlowSegment: Duto flexível redondo:Flexível - Redondo (36)
Type - PredefinedType: FLEXIBLESEGMENT
Pset_DistributionFlowElementCommon - Reference: Flexível - Redondo; sets with these values: 2
Name (Duto flexível redondo:Flexível - Redondo:...) | In | Group
819979 | 2PAV | Mecânica Ar de fornecimento 1
819983 | 2PAV | Mecânica Ar de fornecimento 1
819986 | 2PAV | Mecânica Ar de fornecimento 1
819989 | 2PAV | Mecânica Ar de fornecimento 1
819992 | 2PAV | Mecânica Ar de fornecimento 1
819995 | 2PAV | Mecânica Ar de fornecimento 1
819998 | 2PAV | Mecânica Ar de fornecimento 1
820001 | 2PAV | Mecânica Ar de fornecimento 1
820004 | 2PAV | Mecânica Ar de fornecimento 1
820007 | 2PAV | Mecânica Ar de fornecimento 1
820243 | 2PAV | I 1
820247 | 2PAV | I 1
820250 | 2PAV | I 1
820253 | 2PAV | I 1
820256 | 2PAV | I 1
820259 | 2PAV | I 1
820262 | 2PAV | I 1
820265 | 2PAV | I 1
820268 | 2PAV | I 1
820271 | 2PAV | I 1
914765 | Nível 1 | I 8
914768 | Nível 1 | I 8
914826 | Nível 1 | I 8
914830 | Nível 1 | I 8
946369 | 2PAV | AE 11; I 9
946391 | 2PAV | AE 10; I 10
946513 | 2PAV | AE 9; I 11
946584 | 2PAV | AE 12; I 12
946606 | 2PAV | AE 8; I 13
946766 | 2PAV | AE 26
946816 | 2PAV | AE 6; I 15
946839 | 2PAV | AE 7; I 16
951180 | 2PAV | AE 14; I 17
952361 | 2PAV | AE 15; I 18
952625 | 2PAV | AE 16; I 19
1066909 | 1PAV | AE 17; I 20

# IfcFlowSegment: Duto retangular:Raios cotovelos / torneiras (199)
Pset_DistributionFlowElementCommon - Reference: Raios cotovelos / torneiras; sets with these values: 2
Pset_DuctSegmentTypeCommon - Shape: RECTANGULAR
Pset_FlowSegmentDuctSegment - sets with these values: 2
Name (Duto retangular:Raios cotovelos / torneiras:...) | In | Pset_DuctSegmentTypeCommon, Length (mm) = Pset_FlowSegmentDuctSegment, Length (mm) | Group
829018 | 2PAV | 300 | R 1
829064 | 2PAV | 300 | R 2
831099 | 2PAV | 500 | R 1
831170 | 2PAV | 500 | R 1
831225 | 2PAV | 400 | R 1
831469 | 2PAV | 500 | R 2
831545 | 2PAV | 400 | R 2
832806 | 1PAV | 500 | Mecânica Ar de fornecimento 1
833251 | 2PAV | 850 | R 1
833273 | 2PAV | 850 | R 1
833288 | 2PAV | 900 | R 1
833299 | 2PAV | 950 | R 1
833319 | 2PAV | 850 | R 2
833329 | 2PAV | 850 | R 2
833338 | 2PAV | 900 | R 2
833347 | 2PAV | 950 | R 2
838995 | 1PAV | 500 | Mecânica Ar de fornecimento 1
875422 | LAJE TÉCNICA | 500 | R 2
878356 | LAJE TÉCNICA | 500 | R 2
878405 | LAJE TÉCNICA | 500 | R 2
878431 | LAJE TÉCNICA | 500 | R 1
878439 | LAJE TÉCNICA | 500 | R 1
878469 | LAJE TÉCNICA | 180 | R 1
878479 | LAJE TÉCNICA | 500 | R 1
878614 | LAJE TÉCNICA | 180 | R 2
878816 | LAJE TÉCNICA | 500 | R 2
878860 | LAJE TÉCNICA | 500 | R 1
894785 | 1PAV | 350 | I 5
895242 | 1PAV | 125 | I 5
895264 | 1PAV | 125 | I 5
895284 | 1PAV | 125 | I 5
895308 | 1PAV | 125 | I 5
895330 | 1PAV | 125 | I 5
902786 | 2PAV | 200 | I 6
902793 | 2PAV | 300 | I 6; I 7
902818 | 2PAV | 400 | I 6; I 4
903864 | 2PAV | 400 | I 6
903871 | 2PAV | 400 | I 6
903881 | 2PAV | 400 | I 6
905256 | 2PAV | 125 | EX 2
905274 | 2PAV | 125 | EX 3
906409 | 1PAV | 61.0051 | EX 2
906563 | 1PAV | 100 | EX 2
906570 | 1PAV | 100 | EX 2
906588 | 1PAV | 100 | EX 2
906622 | 1PAV | 100 | EX 2
906687 | TÉRREO +0.32m | 125 | EX 3
906694 | TÉRREO +0.32m | 1108.61 | EX 3
906717 | TÉRREO +0.32m | 125 | EX 2
906726 | TÉRREO +0.32m | 2289.02 | EX 2
907122 | TÉRREO +0.32m | 2473.91 | EX 2; EX 5
907211 | TÉRREO +0.32m | 662.518 | EX 2
908652 | TÉRREO +0.32m | 100 | EX 1
908659 | TÉRREO +0.32m | 175 | EX 1
908865 | TÉRREO +0.32m | 225 | EX 1
908876 | TÉRREO +0.32m | 363.541 | EX 1
909018 | TÉRREO +0.32m | 100 | EX 8
909023 | TÉRREO +0.32m | 150 | EX 8
909281 | TÉRREO +0.32m | 83 | EX 8
909444 | TÉRREO +0.32m | 108 | EX 8
909618 | TÉRREO +0.32m | 150 | EX 8
909626 | TÉRREO +0.32m | 4718.96 | EX 8
909759 | 2PAV | 100 | EX 9
909766 | 2PAV | 125 | EX 9
909811 | 2PAV | 200 | EX 9
909909 | 2PAV | 196.5 | EX 9
910001 | 2PAV | 196.5 | EX 9
910090 | 2PAV | 121.5 | EX 9
910179 | 2PAV | 357.5 | EX 9
910577 | TÉRREO +0.32m | 225 | EX 1
910590 | TÉRREO +0.32m | 4596.03 | EX 1
910736 | 2PAV | 149 | I 6
910820 | 2PAV | 149 | I 6
910905 | 2PAV | 199 | I 6
910989 | 2PAV | 249 | I 6
911629 | TÉRREO +0.32m | 5162.26 | EX 3
911733 | TÉRREO +0.32m | 125 | EX 3
911760 | TÉRREO +0.32m | 150 | EX 2
911889 | TÉRREO +0.32m | 681.057 | EX 2
912497 | 1PAV | 125 | EX 2
912546 | TÉRREO +0.32m | 225 | EX 1
912595 | LAJE TÉCNICA | 150 | EX 8
913915 | TÉRREO +0.32m | 250 | I 8
913974 | TÉRREO +0.32m | 250 | I 8
916132 | TÉRREO +0.32m | 147 | R 3
919055 | 2PAV | 200 | R 5
919121 | 2PAV | 300 | R 5; R 4
919154 | 2PAV | 400 | R 5; R 6
919431 | 2PAV | 249 | R 5
919536 | 2PAV | 199 | R 5
919560 | 2PAV | 149 | R 5
919662 | 2PAV | 149 | R 5
919771 | 2PAV | 500 | R 5
920542 | 2PAV | 200 | AE 26; AE 2; AE 25
920765 | TÉRREO +0.32m | 125 | AE 3; AE 4
921120 | TÉRREO +0.32m | 125 | AE 3
921282 | TÉRREO +0.32m | 100 | AE 3
921361 | TÉRREO +0.32m | 150 | AE 23
921443 | TÉRREO +0.32m | 100 | AE 23
921562 | TÉRREO +0.32m | 100 | AE 23
923649 | TÉRREO +0.32m | 100 | AE 23
923757 | TÉRREO +0.32m | 121.5 | AE 3
923903 | TÉRREO +0.32m | 100 | AE 3
924303 | TÉRREO +0.32m | 134 | AE 23
924467 | TÉRREO +0.32m | 150 | AE 23; AE 1
925216 | 2PAV | 268 | I 6
925420 | 2PAV | 400 | R 5
925507 | 2PAV | 456 | R 5
925648 | 2PAV | 200 | AE 2
945445 | 2PAV | 260 | AE 26; AE 5
945538 | 2PAV | 250 | AE 6
945626 | 2PAV | 254.264 | AE 7
945715 | 2PAV | 277.153 | AE 8
945972 | 2PAV | 310.704 | AE 9
946106 | 2PAV | 260 | AE 10
946171 | 2PAV | 280 | AE 11
946267 | 2PAV | 200 | AE 26
946289 | 2PAV | 277.153 | AE 12
946671 | 2PAV | 200 | AE 26
947193 | TÉRREO +0.32m | 111.233 | R 3
951541 | 2PAV | 150 | AE 2
951548 | 2PAV | 150 | AE 2
951630 | 2PAV | 150 | AE 2
951711 | 2PAV | 450 | AE 2
951878 | 2PAV | 200 | AE 26
952181 | 2PAV | 400 | AE 15
952469 | 2PAV | 350.212 | AE 16
952891 | 2PAV | 175 | AE 26; AE 2
952962 | 2PAV | 200 | AE 26
1064325 | TÉRREO +0.32m | 250 | EX 3
1064339 | TÉRREO +0.32m | 125 | EX 3
1065794 | 2PAV | 400 | R 5
1066105 | TÉRREO +0.32m | 400 | AE 17
1066529 | 1PAV | 50.3972 | AE 13
1067355 | LAJE TÉCNICA | 1000 | AE 18
1067405 | LAJE TÉCNICA | 1000 | AE 19
1067442 | LAJE TÉCNICA | 1000 | AE 20
1067473 | LAJE TÉCNICA | 1114 | AE 21
1067542 | LAJE TÉCNICA | 1677.58 | AE 22
1067636 | 2PAV | 268 | I 6
1067839 | TÉRREO +0.32m | 150 | AE 23
1068259 | TÉRREO +0.32m | 2411.34 | AE 23
1068298 | TÉRREO +0.32m | 4627.62 | AE 23
1068402 | LAJE TÉCNICA | 500 | R 1
1068442 | LAJE TÉCNICA | 850 | R 1
1068606 | LAJE TÉCNICA | 452.2 | R 1
1068740 | LAJE TÉCNICA | 452.2 | R 2
1068853 | LAJE TÉCNICA | 500 | R 2
1068909 | LAJE TÉCNICA | 850 | R 2
1068919 | LAJE TÉCNICA | 500 | R 2
1070058 | 1PAV | 150 | AE 23
1070180 | 1PAV | 65 | AE 23
1070781 | 1PAV | 100 | AE 13
1070788 | 1PAV | 100 | AE 13
1070914 | 1PAV | 936.396 | AE 13
1070924 | 1PAV | 100 | AE 13
1071588 | 1PAV | 200 | AE 13
1072802 | 1PAV | 268 | I 5
1073011 | 1PAV | 268 | I 5
1084572 | 1PAV | 289 | AE 13
1084711 | 1PAV | 289 | AE 13
1084771 | 1PAV | 565 | AE 24
1084845 | 1PAV | 400 | AE 24
1086264 | TÉRREO +0.32m | 200 | AE 23
1088115 | LAJE TÉCNICA | 200 | AE 23
1088122 | LAJE TÉCNICA | 350 | AE 23
1088140 | LAJE TÉCNICA | 200 | AE 23
1088938 | 2PAV | 150 | AE 2
1088944 | 2PAV | 150 | AE 2
1089078 | 2PAV | 200 | AE 26
1089197 | 2PAV | 200 | AE 26
1089317 | 2PAV | 200 | AE 26; AE 2
1089403 | 2PAV | 1359 | AE 26
1089595 | LAJE TÉCNICA | 251.9 | AE 26
1089604 | LAJE TÉCNICA | 251.9 | AE 26
1089648 | 2PAV | 200 | AE 26
1095715 | TÉRREO +0.32m | 147 | I 8
1095771 | TÉRREO +0.32m | 147 | I 8
1113724 | TÉRREO +0.32m | 145.202 | EX 11
1113831 | TÉRREO +0.32m | 200 | EX 11
1113881 | TÉRREO +0.32m | 200 | EX 11
1113951 | TÉRREO +0.32m | 7012 | EX 11
1113963 | TÉRREO +0.32m | 200 | EX 11
1114521 | LAJE TÉCNICA | 2390 | EX 10
1119958 | TÉRREO +0.32m | 200 | I 8
1123811 | TÉRREO +0.32m | 150 | AE 3
1123839 | TÉRREO +0.32m | 150 | AE 3; AE 23
1124044 | TÉRREO +0.32m | 35 | AE 3
1124093 | TÉRREO +0.32m | 35 | AE 3
1126083 | LAJE TÉCNICA | 150 | EX 2
1126090 | LAJE TÉCNICA | 150 | EX 2
1127053 | TÉRREO +0.32m | 45.5 | EX 1
1127072 | TÉRREO +0.32m | 70.5 | EX 1
1127089 | TÉRREO +0.32m | 108 | EX 1
1127271 | TÉRREO +0.32m | 464.79 | EX 8
1127416 | TÉRREO +0.32m | 1390.75 | EX 8
1127545 | LAJE TÉCNICA | 200 | EX 9
1127614 | LAJE TÉCNICA | 200 | EX 9
1127624 | LAJE TÉCNICA | 200 | EX 9

# IfcFlowSegment: Duto retangular:Raios cotovelos / tês (36)
Pset_DistributionFlowElementCommon - Reference: Raios cotovelos / tês; sets with these values: 2
Pset_DuctSegmentTypeCommon - Shape: RECTANGULAR
Pset_FlowSegmentDuctSegment - sets with these values: 2
Name (Duto retangular:Raios cotovelos / tês:...) | In | Pset_DuctSegmentTypeCommon, Length (mm) = Pset_FlowSegmentDuctSegment, Length (mm) | Group
818453 | 2PAV | 500 | Mecânica Ar de fornecimento 1
818485 | 2PAV | 500 | I 1
818510 | 2PAV | 500 | Mecânica Ar de fornecimento 1; I 2
818544 | 2PAV | 500 | I 1; I 3
818567 | 2PAV | 500 | Mecânica Ar de fornecimento 1
818605 | 2PAV | 500 | I 1
832829 | 1PAV | 500 | I 1
837432 | LAJE TÉCNICA | 447 | I 1
837524 | LAJE TÉCNICA | 447 | I 1
837854 | LAJE TÉCNICA | 447 | I 1
837879 | LAJE TÉCNICA | 447 | I 1
837887 | LAJE TÉCNICA | 447 | I 1
837912 | LAJE TÉCNICA | 447 | I 1
838578 | LAJE TÉCNICA | 447 | Mecânica Ar de fornecimento 1
838579 | LAJE TÉCNICA | 447 | Mecânica Ar de fornecimento 1
838582 | LAJE TÉCNICA | 447 | Mecânica Ar de fornecimento 1
838584 | LAJE TÉCNICA | 447 | Mecânica Ar de fornecimento 1
838586 | LAJE TÉCNICA | 447 | Mecânica Ar de fornecimento 1
838587 | LAJE TÉCNICA | 447 | Mecânica Ar de fornecimento 1
873656 | LAJE TÉCNICA | 500 | I 1
874741 | LAJE TÉCNICA | 500 | Mecânica Ar de fornecimento 1
874750 | LAJE TÉCNICA | 500 | Mecânica Ar de fornecimento 1
874806 | LAJE TÉCNICA | 500 | Mecânica Ar de fornecimento 1
874866 | LAJE TÉCNICA | 500 | I 1
874875 | LAJE TÉCNICA | 500 | I 1
875021 | LAJE TÉCNICA | 439.048 | I 1
875039 | LAJE TÉCNICA | 500 | I 1
875102 | LAJE TÉCNICA | 426.056 | Mecânica Ar de fornecimento 1
949734 | 1PAV | 200 | AE 13
951087 | 2PAV | 320 | AE 14
1065626 | 1PAV | 150 | AE 13
1065637 | 1PAV | 400 | AE 13
1065657 | 1PAV | 150 | AE 13
1066695 | 1PAV | 150 | AE 13
1070331 | 1PAV | 200 | AE 13
1071533 | 1PAV | 150 | AE 13

# IfcFlowTerminal: ADLQ-AG-K-T3:DIFUSOR 4 VIAS ADLQ-AG-K T3 (DIÂMETRO 200) (4)
In: TÉRREO +0.32m
Type - Material: <Unnamed>
Pset_DistributionFlowElementCommon - Reference: DIFUSOR 4 VIAS ADLQ-AG-K T3 (DIÂMETRO 200); sets with these values: 2
Group: I 8
Name (ADLQ-AG-K-T3:DIFUSOR 4 VIAS ADLQ-AG-K T3 (DIÂMETRO 200):...)
912745
912785
913396
913450

# IfcFlowTerminal: AH-0-AG 1025x125:AH-0-AG 1025x125 (5)
In: 1PAV
Type - Material: <Unnamed>
Pset_DistributionFlowElementCommon - Reference: AH-0-AG 1025x125; sets with these values: 2
Group: I 5
Name (AH-0-AG 1025x125:AH-0-AG 1025x125:...)
894178
894400
894408
894418
894426

# IfcFlowTerminal: AH-0-AG 1025x225:AH-0-AG 1025x225 (4)
In: 2PAV
Type - Material: <Unnamed>
Pset_DistributionFlowElementCommon - Reference: AH-0-AG 1025x225; sets with these values: 2
Group: I 6
Name (AH-0-AG 1025x225:AH-0-AG 1025x225:...)
902440
902462
902470
902480

# IfcFlowTerminal: AH-0-AG 225x125:AH-0-AG 225x125 (5)
Type - Material: <Unnamed>
Pset_DistributionFlowElementCommon - Reference: AH-0-AG 225x125; sets with these values: 2
Name (AH-0-AG 225x125:AH-0-AG 225x125:...) | In | Group
899065 | TÉRREO +0.32m | AE 3
899070 | TÉRREO +0.32m | AE 3
899104 | TÉRREO +0.32m | AE 3
944957 | 2PAV | AE 9
952135 | 2PAV | AE 15

# IfcFlowTerminal: AH-0-AG 225x75:AE (12)
Type - Material: <Unnamed>
Pset_DistributionFlowElementCommon - Reference: AE; sets with these values: 2
Name (AH-0-AG 225x75:AE:...) | In | Group
898182 | TÉRREO +0.32m | AE 3
899176 | TÉRREO +0.32m | AE 23
944860 | 2PAV | AE 10
944867 | 2PAV | AE 11
944984 | 2PAV | AE 8
945242 | 2PAV | AE 26
945249 | 2PAV | AE 6
945256 | 2PAV | AE 7
946288 | 2PAV | AE 12
950659 | 2PAV | AE 14
952421 | 2PAV | AE 16
1065997 | TÉRREO +0.32m | AE 17

# IfcFlowTerminal: AH-0-AG 325x225:AH-0-AG 325x225 (2)
In: 1PAV
Type - Material: <Unnamed>
Pset_DistributionFlowElementCommon - Reference: AH-0-AG 325x225; sets with these values: 2
Name (AH-0-AG 325x225:AH-0-AG 325x225:...) | Group
1069948 | AE 23
1070992 | AE 13

# IfcFlowTerminal: AH-0-AG 625x125:AH-0-AG 625x125, AH-0-AG 625x125:AH-0-AG 625x125:1065355
In: 1PAV
Type - Material: <Unnamed>
Pset_DistributionFlowElementCommon - Reference: AH-0-AG 625x125; sets with these values: 2
Group: AE 13

# IfcFlowTerminal: AWK 497x397:AWK 497x397, AWK 497x397:AWK 497x397:1085687
In: 1PAV
Type - Material: <Unnamed>
Pset_DistributionFlowElementCommon - Reference: AWK 497x397; sets with these values: 2
Group: AE 24

# IfcFlowTerminal: GRELHA AR-AG 1025x225:GRELHA AR-AG 1025x225 (4)
In: 2PAV
Type - Material: <Unnamed>
Pset_DistributionFlowElementCommon - Reference: GRELHA AR-AG 1025x225; sets with these values: 2
Group: R 5
Name (GRELHA AR-AG 1025x225:GRELHA AR-AG 1025x225:...)
919003
919010
919029
919037

# IfcFlowTerminal: GRELHA AR-AG 1025x325:GRELHA AR-0-AG 1025x325, GRELHA AR-AG 1025x325:GRELHA AR-0-AG 1025x325:917817
In: TÉRREO +0.32m
Type - Material: <Unnamed>
Pset_DistributionFlowElementCommon - Reference: GRELHA AR-0-AG 1025x325; sets with these values: 2
Group: R 3

# IfcFlowTerminal: GRELHA AR-AG 1025x525:GRELHA AR-AG 1025x525, GRELHA AR-AG 1025x525:GRELHA AR-AG 1025x525:896588
In: TÉRREO +0.32m
Type - Material: <Unnamed>
Pset_DistributionFlowElementCommon - Reference: GRELHA AR-AG 1025x525; sets with these values: 2

# IfcFlowTerminal: GRELHA AR-AG 1225x425:GRELHA AR-AG 1225x425 (8)
In: 2PAV
Type - Material: <Unnamed>
Pset_DistributionFlowElementCommon - Reference: GRELHA AR-AG 1225x425; sets with these values: 2
Name (GRELHA AR-AG 1225x425:GRELHA AR-AG 1225x425:...) | Group
830645 | R 1
830682 | R 1
830692 | R 1
830700 | R 1
830708 | R 2
830732 | R 2
830742 | R 2
830750 | R 2

# IfcFlowTerminal: GRELHA AR-AG 225x125:GRELHA AR-AG 225x125 (9)
Type - Material: <Unnamed>
Pset_DistributionFlowElementCommon - Reference: GRELHA AR-AG 225x125; sets with these values: 2
Name (GRELHA AR-AG 225x125:GRELHA AR-AG 225x125:...) | In | Group
904946 | 1PAV | EX 2
905042 | TÉRREO +0.32m | EX 2
905049 | TÉRREO +0.32m | EX 3
905104 | 2PAV | EX 3
905111 | 2PAV | EX 2
906351 | 1PAV | EX 2
908985 | TÉRREO +0.32m | EX 8
908992 | TÉRREO +0.32m | EX 8
909725 | 2PAV | EX 9

# IfcFlowTerminal: GRELHA AR-AG 425x125:GRELHA AR-AG 425x125 (5)
Type - Material: <Unnamed>
Pset_DistributionFlowElementCommon - Reference: GRELHA AR-AG 425x125; sets with these values: 2
Name (GRELHA AR-AG 425x125:GRELHA AR-AG 425x125:...) | In | Group
908131 | TÉRREO +0.32m | EX 1
908138 | TÉRREO +0.32m | EX 1
908145 | TÉRREO +0.32m | EX 1
909680 | 2PAV | EX 9
909709 | 2PAV | EX 9

# IfcFlowTerminal: Ralo Conico Montado - Caixas e Ralos - Esgoto - MEP - Tigre:Branco c/ grelha branca - 100 x 40 (2)
In: LAJE TÉCNICA
Type - Material: <Unnamed>
Type - Pset_ManufacturerTypeInformation - Manufacturer: © Tigre S/A
Pset_DistributionFlowElementCommon - Reference: Branco c/ grelha branca - 100 x 40; sets with these values: 2
Name (Ralo Conico Montado - Caixas e Ralos - Esgoto - MEP - Tigre:Branco c/ grelha branca - 100 x 40:...)
888307
888325

# IfcFlowTerminal: VD-HM 600:VD-HM 600 (20)
In: 2PAV
Type - Material: <Unnamed>
Pset_DistributionFlowElementCommon - Reference: VD-HM 600; sets with these values: 2
Name (VD-HM 600:VD-HM 600:...) | Group
806109 | Mecânica Ar de fornecimento 1
806130 | Mecânica Ar de fornecimento 1
806138 | I 1
806146 | I 1
806156 | I 1
806166 | I 1
806176 | I 1
806184 | I 1
806205 | I 1
806206 | I 1
806207 | I 1
806208 | I 1
806216 | Mecânica Ar de fornecimento 1
806217 | Mecânica Ar de fornecimento 1
806218 | Mecânica Ar de fornecimento 1
806219 | Mecânica Ar de fornecimento 1
806227 | Mecânica Ar de fornecimento 1
806228 | Mecânica Ar de fornecimento 1
806229 | Mecânica Ar de fornecimento 1
806230 | Mecânica Ar de fornecimento 1

# IfcFlowTerminal: grelha genérica:grelha genérica (3)
Type - Material: <Unnamed>
Pset_DistributionFlowElementCommon - Reference: grelha genérica; sets with these values: 2
Name (grelha genérica:grelha genérica:...) | In | Group
922506 | TÉRREO +0.32m | AE 23
951662 | 2PAV | AE 2
1066880 | 1PAV | AE 13

# IfcOpeningElement: Opening (9)
Pset_OpeningElementCommon - sets with these values: 2
Name | In | Reference
V8 duto alta 20-33.5kW:28kW:869751:1 | 2PAV | 28kW
V8 duto alta 20-33.5kW:28kW:869751:2 | 2PAV | 28kW
V8 duto alta 20-33.5kW:28kW:869751:3 | 2PAV | 28kW
V8 duto alta 20-33.5kW:28kW:869751:4 | 2PAV | 28kW
V8 duto alta 20-33.5kW:28kW:882826:1 | 1PAV | 28kW
V8 duto alta 20-33.5kW:28kW:882826:2 | 1PAV | 28kW
V8 duto alta 20-33.5kW:28kW:882826:3 | 1PAV | 28kW
V8 duto alta 20-33.5kW:28kW:882826:4 | 1PAV | 28kW
Parede básica:Genérico - 150 mm Tijolo:1081882 | 2PAV | SPLITVENT G4+M5

# IfcSlab: Piso:Genérico 150 mm, Piso:Genérico 150 mm:872462
In: LAJE TÉCNICA
Type - PredefinedType: FLOOR; Material: Material pré-definido de piso 150 mm
Pset_QuantityTakeOff - Reference: Genérico 150 mm; sets with these values: 2
Pset_SlabCommon - Reference: Genérico 150 mm; IsExternal: no; LoadBearing: no; PitchAngle: 0 deg

# IfcWallStandardCase: Parede básica:Genérico - 150 mm, Parede básica:Genérico - 150 mm:1096647
In: TÉRREO +0.32m
Type - PredefinedType: STANDARD; Material: Material pré-definido de parede 150 mm
Pset_QuantityTakeOff - Reference: Genérico - 150 mm; sets with these values: 2
Pset_WallCommon - LoadBearing: no; IsExternal: yes; ExtendToStructure: no; Reference: Genérico - 150 mm

# IfcWallStandardCase: Parede básica:Genérico - 150 mm Tijolo, Parede básica:Genérico - 150 mm Tijolo:1081882
In: 2PAV
Type - PredefinedType: STANDARD; Material: Tijolo, Comum 150 mm
Type - Pset_WallCommon - ThermalTransmittance: 3.6 kg/K/s3
Pset_QuantityTakeOff - Reference: Genérico - 150 mm Tijolo; sets with these values: 2
Pset_WallCommon - IsExternal: yes; ExtendToStructure: no; Reference: Genérico - 150 mm Tijolo; LoadBearing: yes

# IfcWallStandardCase: Parede básica:Genérico - 200 mm (4)
In: LAJE TÉCNICA
Type - PredefinedType: STANDARD; Material: Material pré-definido de parede 200 mm
Pset_QuantityTakeOff - Reference: Genérico - 200 mm; sets with these values: 2
Pset_WallCommon - LoadBearing: no; Reference: Genérico - 200 mm; IsExternal: yes; ExtendToStructure: no
Name (Parede básica:Genérico - 200 mm:...)
903197
903256
903355
903356
